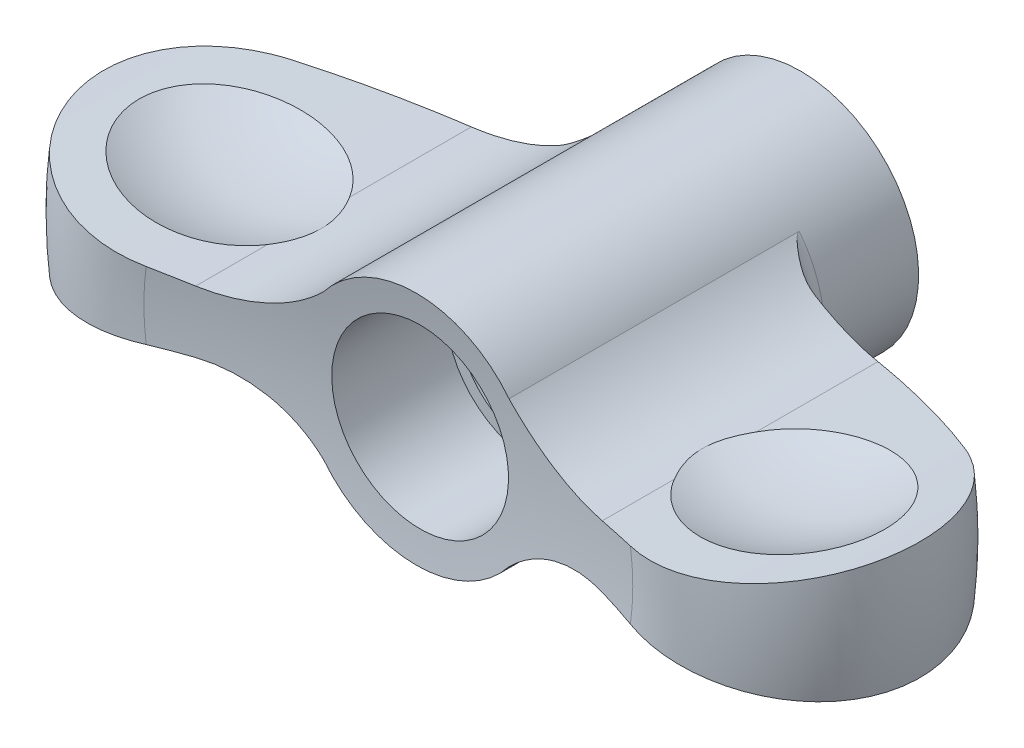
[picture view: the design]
ISO-10303-21;
HEADER;
FILE_DESCRIPTION(('STEP AP214'),'2;1');
FILE_NAME('part.step','',(''),(''),'','','');
FILE_SCHEMA(('AUTOMOTIVE_DESIGN { 1 0 10303 214 1 1 1 1 }'));
ENDSEC;
DATA;
#1=APPLICATION_CONTEXT('core data for automotive mechanical design processes');
#2=APPLICATION_PROTOCOL_DEFINITION('international standard','automotive_design',2000,#1);
#3=PRODUCT_CONTEXT('',#1,'mechanical');
#4=PRODUCT('Part','Part','',(#3));
#5=PRODUCT_RELATED_PRODUCT_CATEGORY('part','',(#4));
#6=PRODUCT_DEFINITION_FORMATION('','',#4);
#7=PRODUCT_DEFINITION_CONTEXT('part definition',#1,'design');
#8=PRODUCT_DEFINITION('design','',#6,#7);
#9=PRODUCT_DEFINITION_SHAPE('','',#8);
#10=(LENGTH_UNIT() NAMED_UNIT(*) SI_UNIT(.MILLI.,.METRE.));
#11=(NAMED_UNIT(*) PLANE_ANGLE_UNIT() SI_UNIT($,.RADIAN.));
#12=(NAMED_UNIT(*) SI_UNIT($,.STERADIAN.) SOLID_ANGLE_UNIT());
#13=UNCERTAINTY_MEASURE_WITH_UNIT(LENGTH_MEASURE(1.E-05),#10,'distance_accuracy_value','');
#14=(GEOMETRIC_REPRESENTATION_CONTEXT(3) GLOBAL_UNCERTAINTY_ASSIGNED_CONTEXT((#13)) GLOBAL_UNIT_ASSIGNED_CONTEXT((#10,
#11,#12)) REPRESENTATION_CONTEXT('',''));
#15=CARTESIAN_POINT('',(0.,0.,0.));
#16=DIRECTION('',(0.,0.,1.));
#17=DIRECTION('',(1.,0.,0.));
#18=AXIS2_PLACEMENT_3D('',#15,#16,#17);
#19=CARTESIAN_POINT('',(0.,0.,8.));
#20=DIRECTION('',(0.,0.,-1.));
#21=DIRECTION('',(0.,1.,0.));
#22=AXIS2_PLACEMENT_3D('',#19,#20,#21);
#23=TOROIDAL_SURFACE('',#22,11.8,1.80000000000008);
#24=CARTESIAN_POINT('',(-10.9364004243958,-3.94636818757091,9.7916319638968));
#25=CARTESIAN_POINT('',(-10.8241185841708,-4.00370429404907,9.78325234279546));
#26=CARTESIAN_POINT('',(-10.7132133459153,-4.06254400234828,9.76897182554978));
#27=CARTESIAN_POINT('',(-10.4947965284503,-4.18269546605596,9.73031315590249));
#28=CARTESIAN_POINT('',(-10.3872790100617,-4.2440024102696,9.70595387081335));
#29=CARTESIAN_POINT('',(-10.1765147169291,-4.368381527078,9.64897611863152));
#30=CARTESIAN_POINT('',(-10.0732455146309,-4.43144032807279,9.61641003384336));
#31=CARTESIAN_POINT('',(-9.87034998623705,-4.55941800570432,9.54423053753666));
#32=CARTESIAN_POINT('',(-9.7707251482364,-4.62433762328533,9.50461428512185));
#33=CARTESIAN_POINT('',(-9.55076497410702,-4.77218804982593,9.4087986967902));
#34=CARTESIAN_POINT('',(-9.43146470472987,-4.8555710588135,9.35092807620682));
#35=CARTESIAN_POINT('',(-9.19845422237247,-5.02453572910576,9.22749490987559));
#36=CARTESIAN_POINT('',(-9.08474708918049,-5.11011856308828,9.16192819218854));
#37=CARTESIAN_POINT('',(-8.8958350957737,-5.25740071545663,9.04459290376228));
#38=CARTESIAN_POINT('',(-8.81922141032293,-5.31864764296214,8.99450670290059));
#39=CARTESIAN_POINT('',(-8.66877804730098,-5.44185241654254,8.89113944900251));
#40=CARTESIAN_POINT('',(-8.5949480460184,-5.50381017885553,8.83785876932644));
#41=CARTESIAN_POINT('',(-8.47417990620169,-5.60755853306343,8.74594898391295));
#42=CARTESIAN_POINT('',(-8.42641392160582,-5.64925103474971,8.7082931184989));
#43=CARTESIAN_POINT('',(-8.33242521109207,-5.73256077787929,8.63109723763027));
#44=CARTESIAN_POINT('',(-8.28620142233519,-5.77417805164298,8.59155856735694));
#45=CARTESIAN_POINT('',(-8.21125367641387,-5.8426693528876,8.52388347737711));
#46=CARTESIAN_POINT('',(-8.18198002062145,-5.86968993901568,8.49650386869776));
#47=CARTESIAN_POINT('',(-8.12444979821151,-5.92330159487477,8.44010631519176));
#48=CARTESIAN_POINT('',(-8.09619524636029,-5.94989176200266,8.41108538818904));
#49=CARTESIAN_POINT('',(-8.04234032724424,-6.00103726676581,8.35179046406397));
#50=CARTESIAN_POINT('',(-8.01668026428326,-6.02563150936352,8.32160361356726));
#51=CARTESIAN_POINT('',(-7.96790958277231,-6.0727602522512,8.2576023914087));
#52=CARTESIAN_POINT('',(-7.94479257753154,-6.0952998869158,8.22379754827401));
#53=CARTESIAN_POINT('',(-7.91701322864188,-6.12255630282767,8.17250880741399));
#54=CARTESIAN_POINT('',(-7.90975258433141,-6.12970126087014,8.15779331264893));
#55=CARTESIAN_POINT('',(-7.89665438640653,-6.14261741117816,8.12727584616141));
#56=CARTESIAN_POINT('',(-7.89080740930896,-6.14839769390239,8.11148202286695));
#57=CARTESIAN_POINT('',(-7.88158226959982,-6.15753000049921,8.08013275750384));
#58=CARTESIAN_POINT('',(-7.87802903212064,-6.16105398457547,8.06468423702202));
#59=CARTESIAN_POINT('',(-7.87307566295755,-6.16597001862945,8.03281428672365));
#60=CARTESIAN_POINT('',(-7.87172008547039,-6.16731795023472,8.01637956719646));
#61=CARTESIAN_POINT('',(-7.8717856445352,-6.16725149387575,7.9998));
#62=B_SPLINE_CURVE_WITH_KNOTS('',3,(#24,#25,#26,#27,#28,#29,#30,#31,#32,#33,#34,#35,#36,#37,#38,
#39,#40,#41,#42,#43,#44,#45,#46,#47,#48,#49,#50,#51,#52,#53,#54,#55,#56,#57,#58,#59,#60,#61),
.UNSPECIFIED.,.F.,.F.,(4,2,2,2,2,2,2,2,2,2,2,2,2,2,2,2,2,2,4),(0.,0.378686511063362,
0.756667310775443,1.13229407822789,1.50807255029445,1.97761636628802,2.44741590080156,
2.77774393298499,3.10803343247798,3.3292309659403,3.55027276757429,3.6952714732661,
3.84054267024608,3.980393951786,4.11988557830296,4.17347981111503,4.2267062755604,
4.27513325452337,4.3245302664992),.UNSPECIFIED.);
#63=CARTESIAN_POINT('',(-10.9337221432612,-3.94773654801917,9.7914319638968));
#64=VERTEX_POINT('',#63);
#65=CARTESIAN_POINT('',(-7.8717855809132,-6.16725155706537,8.));
#66=VERTEX_POINT('',#65);
#67=EDGE_CURVE('E491',#64,#66,#62,.T.);
#68=ORIENTED_EDGE('',*,*,#67,.F.);
#69=CARTESIAN_POINT('',(0.,0.,9.7914319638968));
#70=DIRECTION('',(0.,0.,-1.));
#71=DIRECTION('',(0.,1.,0.));
#72=AXIS2_PLACEMENT_3D('',#69,#70,#71);
#73=CIRCLE('',#72,11.6245818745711);
#74=CARTESIAN_POINT('',(-10.9337221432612,3.94773654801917,9.7914319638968));
#75=VERTEX_POINT('',#74);
#76=EDGE_CURVE('E513',#64,#75,#73,.T.);
#77=ORIENTED_EDGE('',*,*,#76,.T.);
#78=CARTESIAN_POINT('',(-10.9364004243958,3.94636818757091,9.7916319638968));
#79=CARTESIAN_POINT('',(-10.8241185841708,4.00370429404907,9.78325234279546));
#80=CARTESIAN_POINT('',(-10.7132133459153,4.06254400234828,9.76897182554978));
#81=CARTESIAN_POINT('',(-10.4947965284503,4.18269546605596,9.73031315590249));
#82=CARTESIAN_POINT('',(-10.3872790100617,4.24400241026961,9.70595387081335));
#83=CARTESIAN_POINT('',(-10.1765147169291,4.368381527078,9.64897611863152));
#84=CARTESIAN_POINT('',(-10.0732455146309,4.4314403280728,9.61641003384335));
#85=CARTESIAN_POINT('',(-9.87034998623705,4.55941800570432,9.54423053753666));
#86=CARTESIAN_POINT('',(-9.7707251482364,4.62433762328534,9.50461428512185));
#87=CARTESIAN_POINT('',(-9.55076497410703,4.77218804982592,9.4087986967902));
#88=CARTESIAN_POINT('',(-9.4314647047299,4.85557105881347,9.35092807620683));
#89=CARTESIAN_POINT('',(-9.19845422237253,5.02453572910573,9.22749490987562));
#90=CARTESIAN_POINT('',(-9.08474708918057,5.11011856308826,9.16192819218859));
#91=CARTESIAN_POINT('',(-8.89583509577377,5.25740071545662,9.04459290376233));
#92=CARTESIAN_POINT('',(-8.81922141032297,5.31864764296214,8.99450670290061));
#93=CARTESIAN_POINT('',(-8.66877804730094,5.44185241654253,8.89113944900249));
#94=CARTESIAN_POINT('',(-8.59494804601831,5.50381017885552,8.83785876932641));
#95=CARTESIAN_POINT('',(-8.47417990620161,5.60755853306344,8.74594898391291));
#96=CARTESIAN_POINT('',(-8.42641392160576,5.64925103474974,8.70829311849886));
#97=CARTESIAN_POINT('',(-8.33242521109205,5.73256077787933,8.63109723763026));
#98=CARTESIAN_POINT('',(-8.28620142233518,5.774178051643,8.59155856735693));
#99=CARTESIAN_POINT('',(-8.21125367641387,5.8426693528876,8.52388347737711));
#100=CARTESIAN_POINT('',(-8.18198002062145,5.86968993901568,8.49650386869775));
#101=CARTESIAN_POINT('',(-8.1244497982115,5.92330159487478,8.44010631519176));
#102=CARTESIAN_POINT('',(-8.09619524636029,5.94989176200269,8.41108538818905));
#103=CARTESIAN_POINT('',(-8.04234032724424,6.00103726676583,8.35179046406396));
#104=CARTESIAN_POINT('',(-8.01668026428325,6.02563150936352,8.32160361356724));
#105=CARTESIAN_POINT('',(-7.9679095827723,6.07276025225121,8.25760239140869));
#106=CARTESIAN_POINT('',(-7.94479257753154,6.09529988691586,8.22379754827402));
#107=CARTESIAN_POINT('',(-7.91701322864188,6.12255630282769,8.17250880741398));
#108=CARTESIAN_POINT('',(-7.90975258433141,6.12970126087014,8.15779331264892));
#109=CARTESIAN_POINT('',(-7.89665438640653,6.14261741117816,8.1272758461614));
#110=CARTESIAN_POINT('',(-7.89080740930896,6.14839769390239,8.11148202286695));
#111=CARTESIAN_POINT('',(-7.88158226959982,6.15753000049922,8.08013275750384));
#112=CARTESIAN_POINT('',(-7.87802903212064,6.16105398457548,8.06468423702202));
#113=CARTESIAN_POINT('',(-7.87307566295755,6.16597001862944,8.03281428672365));
#114=CARTESIAN_POINT('',(-7.8717200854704,6.16731795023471,8.01637956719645));
#115=CARTESIAN_POINT('',(-7.8717856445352,6.16725149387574,7.9998));
#116=B_SPLINE_CURVE_WITH_KNOTS('',3,(#78,#79,#80,#81,#82,#83,#84,#85,#86,#87,#88,#89,#90,#91,
#92,#93,#94,#95,#96,#97,#98,#99,#100,#101,#102,#103,#104,#105,#106,#107,#108,#109,#110,#111,
#112,#113,#114,#115),.UNSPECIFIED.,.F.,.F.,(4,2,2,2,2,2,2,2,2,2,2,2,2,2,2,2,2,2,4),(0.,
0.378686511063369,0.756667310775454,1.1322940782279,1.50807255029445,1.97761636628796,
2.44741590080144,2.77774393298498,3.10803343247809,3.32923096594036,3.55027276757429,
3.6952714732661,3.84054267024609,3.98039395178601,4.11988557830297,4.17347981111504,
4.22670627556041,4.27513325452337,4.3245302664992),.UNSPECIFIED.);
#117=CARTESIAN_POINT('',(-7.8717855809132,6.16725155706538,8.));
#118=VERTEX_POINT('',#117);
#119=EDGE_CURVE('E318',#75,#118,#116,.T.);
#120=ORIENTED_EDGE('',*,*,#119,.T.);
#121=CARTESIAN_POINT('',(0.,0.,8.));
#122=DIRECTION('',(0.,0.,-1.));
#123=DIRECTION('',(0.,1.,0.));
#124=AXIS2_PLACEMENT_3D('',#121,#122,#123);
#125=CIRCLE('',#124,10.);
#126=EDGE_CURVE('E438',#66,#118,#125,.T.);
#127=ORIENTED_EDGE('',*,*,#126,.F.);
#128=EDGE_LOOP('',(#68,#77,#120,#127));
#129=FACE_BOUND('',#128,.T.);
#130=ADVANCED_FACE('F14',(#129),#23,.F.);
#131=CARTESIAN_POINT('',(0.,0.,60.3122983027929));
#132=DIRECTION('',(0.,0.,-1.));
#133=DIRECTION('',(0.,1.,0.));
#134=AXIS2_PLACEMENT_3D('',#131,#132,#133);
#135=DEGENERATE_TOROIDAL_SURFACE('',#134,6.6775474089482,50.7624968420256,.T.);
#136=ORIENTED_EDGE('',*,*,#76,.F.);
#137=CARTESIAN_POINT('',(-6.5467060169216,-7.72330133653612,9.66697769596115));
#138=CARTESIAN_POINT('',(-6.64591288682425,-7.58492422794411,9.66416255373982));
#139=CARTESIAN_POINT('',(-6.74799440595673,-7.44862247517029,9.661900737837));
#140=CARTESIAN_POINT('',(-6.95774811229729,-7.18037757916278,9.65844214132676));
#141=CARTESIAN_POINT('',(-7.06542027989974,-7.04843442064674,9.6572453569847));
#142=CARTESIAN_POINT('',(-7.39653737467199,-6.6595102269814,9.65519040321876));
#143=CARTESIAN_POINT('',(-7.62812663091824,-6.40937348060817,9.65586643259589));
#144=CARTESIAN_POINT('',(-8.11129299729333,-5.92925394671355,9.66138002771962));
#145=CARTESIAN_POINT('',(-8.36287299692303,-5.69927408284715,9.66621819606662));
#146=CARTESIAN_POINT('',(-8.88421895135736,-5.26109545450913,9.68055080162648));
#147=CARTESIAN_POINT('',(-9.15398440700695,-5.05289609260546,9.69004511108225));
#148=CARTESIAN_POINT('',(-9.70731186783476,-4.66146851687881,9.71434109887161));
#149=CARTESIAN_POINT('',(-9.99073342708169,-4.47803881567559,9.72909588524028));
#150=CARTESIAN_POINT('',(-10.5714417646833,-4.13530031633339,9.76473262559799));
#151=CARTESIAN_POINT('',(-10.8687285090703,-3.97599145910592,9.78561456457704));
#152=CARTESIAN_POINT('',(-11.4746831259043,-3.68269992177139,9.83420440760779));
#153=CARTESIAN_POINT('',(-11.7833407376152,-3.54869504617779,9.86190627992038));
#154=CARTESIAN_POINT('',(-12.4099583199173,-3.30668939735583,9.92468529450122));
#155=CARTESIAN_POINT('',(-12.72791823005,-3.19868845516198,9.95976238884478));
#156=CARTESIAN_POINT('',(-13.3702784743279,-3.00943594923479,10.0375625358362));
#157=CARTESIAN_POINT('',(-13.694668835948,-2.92814595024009,10.080274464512));
#158=CARTESIAN_POINT('',(-14.3479208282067,-2.7924555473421,10.173495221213));
#159=CARTESIAN_POINT('',(-14.6767824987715,-2.73805538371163,10.2240041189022));
#160=CARTESIAN_POINT('',(-15.3369192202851,-2.65620760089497,10.3328061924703));
#161=CARTESIAN_POINT('',(-15.6681964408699,-2.62878831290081,10.3911074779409));
#162=CARTESIAN_POINT('',(-16.3304789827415,-2.60086726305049,10.5152293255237));
#163=CARTESIAN_POINT('',(-16.6614842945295,-2.60036640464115,10.5810501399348));
#164=CARTESIAN_POINT('',(-17.3240428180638,-2.62605289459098,10.7205107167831));
#165=CARTESIAN_POINT('',(-17.6555720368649,-2.65249066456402,10.7942180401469));
#166=CARTESIAN_POINT('',(-18.3138495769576,-2.73187573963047,10.9484805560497));
#167=CARTESIAN_POINT('',(-18.6405974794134,-2.78482535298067,11.0290363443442));
#168=CARTESIAN_POINT('',(-19.2867879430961,-2.91642655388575,11.1963521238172));
#169=CARTESIAN_POINT('',(-19.6062391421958,-2.99504586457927,11.2831042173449));
#170=CARTESIAN_POINT('',(-20.2362844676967,-3.17708996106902,11.4622866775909));
#171=CARTESIAN_POINT('',(-20.5468805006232,-3.28050936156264,11.5547158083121));
#172=CARTESIAN_POINT('',(-20.8521318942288,-3.39588894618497,11.6496949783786));
#173=B_SPLINE_CURVE_WITH_KNOTS('',3,(#137,#138,#139,#140,#141,#142,#143,#144,#145,#146,#147,
#148,#149,#150,#151,#152,#153,#154,#155,#156,#157,#158,#159,#160,#161,#162,#163,#164,#165,#166,
#167,#168,#169,#170,#171,#172),.UNSPECIFIED.,.F.,.F.,(4,2,2,2,2,2,2,2,2,2,2,2,2,2,2,2,2,4),(0.,
0.510785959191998,1.02157012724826,2.04291399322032,3.06440575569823,4.08586949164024,
5.09844663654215,6.11102130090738,7.12270361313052,8.13437935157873,9.14459291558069,
10.1548155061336,11.1660977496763,12.1774139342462,13.1982178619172,14.2191106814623,
15.2387247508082,16.2581176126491),.UNSPECIFIED.);
#174=CARTESIAN_POINT('',(-17.2513916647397,-2.62600423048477,10.7060191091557));
#175=VERTEX_POINT('',#174);
#176=EDGE_CURVE('E485',#64,#175,#173,.T.);
#177=ORIENTED_EDGE('',*,*,#176,.T.);
#178=CARTESIAN_POINT('',(-28.5420587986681,-3.86093353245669,14.6248916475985));
#179=CARTESIAN_POINT('',(-28.0949251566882,-3.78973654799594,14.4056959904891));
#180=CARTESIAN_POINT('',(-27.6441940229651,-3.72065339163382,14.1932196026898));
#181=CARTESIAN_POINT('',(-26.7359054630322,-3.58698745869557,13.7818878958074));
#182=CARTESIAN_POINT('',(-26.2783480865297,-3.52240464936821,13.583032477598));
#183=CARTESIAN_POINT('',(-24.8998297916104,-3.33633398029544,13.0087706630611));
#184=CARTESIAN_POINT('',(-23.9692804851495,-3.22192463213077,12.6538347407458));
#185=CARTESIAN_POINT('',(-22.0863023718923,-3.01405683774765,12.0002442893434));
#186=CARTESIAN_POINT('',(-21.133873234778,-2.92059870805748,11.701590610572));
#187=CARTESIAN_POINT('',(-19.6898454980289,-2.79722984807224,11.296179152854));
#188=CARTESIAN_POINT('',(-19.2049108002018,-2.75884755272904,11.1679139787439));
#189=CARTESIAN_POINT('',(-18.2309836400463,-2.68796520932,10.9259763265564));
#190=CARTESIAN_POINT('',(-17.7419911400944,-2.65546521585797,10.8123039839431));
#191=CARTESIAN_POINT('',(-17.2511916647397,-2.6259922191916,10.7059757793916));
#192=B_SPLINE_CURVE_WITH_KNOTS('',3,(#178,#179,#180,#181,#182,#183,#184,#185,#186,#187,#188,
#189,#190,#191),.UNSPECIFIED.,.F.,.F.,(4,2,2,2,2,2,4),(0.,1.50898291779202,3.01795485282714,
6.0232908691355,9.02867228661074,10.5376740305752,12.0466897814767),.UNSPECIFIED.);
#193=CARTESIAN_POINT('',(-28.5416508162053,-3.86086857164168,14.6246916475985));
#194=VERTEX_POINT('',#193);
#195=EDGE_CURVE('E524',#194,#175,#192,.T.);
#196=ORIENTED_EDGE('',*,*,#195,.F.);
#197=CARTESIAN_POINT('',(0.,0.,14.6246916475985));
#198=DIRECTION('',(0.,0.,-1.));
#199=DIRECTION('',(0.,1.,0.));
#200=AXIS2_PLACEMENT_3D('',#197,#198,#199);
#201=CIRCLE('',#200,28.8015995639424);
#202=CARTESIAN_POINT('',(-28.5416508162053,3.86086857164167,14.6246916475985));
#203=VERTEX_POINT('',#202);
#204=EDGE_CURVE('E511',#194,#203,#201,.T.);
#205=ORIENTED_EDGE('',*,*,#204,.T.);
#206=CARTESIAN_POINT('',(-28.5420587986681,3.86093353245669,14.6248916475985));
#207=CARTESIAN_POINT('',(-28.0949251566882,3.78973654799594,14.4056959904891));
#208=CARTESIAN_POINT('',(-27.6441940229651,3.72065339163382,14.1932196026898));
#209=CARTESIAN_POINT('',(-26.7359054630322,3.58698745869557,13.7818878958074));
#210=CARTESIAN_POINT('',(-26.2783480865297,3.5224046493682,13.583032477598));
#211=CARTESIAN_POINT('',(-24.8998297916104,3.33633398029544,13.0087706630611));
#212=CARTESIAN_POINT('',(-23.9692804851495,3.22192463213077,12.6538347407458));
#213=CARTESIAN_POINT('',(-22.0863023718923,3.01405683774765,12.0002442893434));
#214=CARTESIAN_POINT('',(-21.133873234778,2.92059870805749,11.701590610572));
#215=CARTESIAN_POINT('',(-19.6898454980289,2.79722984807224,11.296179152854));
#216=CARTESIAN_POINT('',(-19.2049108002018,2.75884755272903,11.1679139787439));
#217=CARTESIAN_POINT('',(-18.2309836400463,2.68796520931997,10.9259763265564));
#218=CARTESIAN_POINT('',(-17.7419911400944,2.65546521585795,10.8123039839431));
#219=CARTESIAN_POINT('',(-17.2511916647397,2.62599221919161,10.7059757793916));
#220=B_SPLINE_CURVE_WITH_KNOTS('',3,(#206,#207,#208,#209,#210,#211,#212,#213,#214,#215,#216,
#217,#218,#219),.UNSPECIFIED.,.F.,.F.,(4,2,2,2,2,2,4),(0.,1.50898291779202,3.01795485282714,
6.0232908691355,9.02867228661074,10.5376740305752,12.0466897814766),.UNSPECIFIED.);
#221=CARTESIAN_POINT('',(-17.2513916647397,2.62600423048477,10.7060191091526));
#222=VERTEX_POINT('',#221);
#223=EDGE_CURVE('E332',#203,#222,#220,.T.);
#224=ORIENTED_EDGE('',*,*,#223,.T.);
#225=CARTESIAN_POINT('',(-6.5467060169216,7.72330133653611,9.66697769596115));
#226=CARTESIAN_POINT('',(-6.64591288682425,7.5849242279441,9.66416255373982));
#227=CARTESIAN_POINT('',(-6.74799440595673,7.44862247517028,9.661900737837));
#228=CARTESIAN_POINT('',(-6.9577481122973,7.18037757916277,9.65844214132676));
#229=CARTESIAN_POINT('',(-7.06542027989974,7.04843442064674,9.6572453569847));
#230=CARTESIAN_POINT('',(-7.39653737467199,6.65951022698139,9.65519040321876));
#231=CARTESIAN_POINT('',(-7.62812663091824,6.40937348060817,9.65586643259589));
#232=CARTESIAN_POINT('',(-8.11129299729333,5.92925394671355,9.66138002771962));
#233=CARTESIAN_POINT('',(-8.36287299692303,5.69927408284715,9.66621819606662));
#234=CARTESIAN_POINT('',(-8.88421895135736,5.26109545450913,9.68055080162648));
#235=CARTESIAN_POINT('',(-9.15398440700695,5.05289609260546,9.69004511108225));
#236=CARTESIAN_POINT('',(-9.70731186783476,4.66146851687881,9.71434109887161));
#237=CARTESIAN_POINT('',(-9.99073342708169,4.47803881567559,9.72909588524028));
#238=CARTESIAN_POINT('',(-10.5714417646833,4.13530031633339,9.76473262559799));
#239=CARTESIAN_POINT('',(-10.8687285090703,3.97599145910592,9.78561456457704));
#240=CARTESIAN_POINT('',(-11.4746831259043,3.68269992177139,9.83420440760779));
#241=CARTESIAN_POINT('',(-11.7833407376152,3.54869504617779,9.86190627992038));
#242=CARTESIAN_POINT('',(-12.4099583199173,3.30668939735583,9.92468529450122));
#243=CARTESIAN_POINT('',(-12.72791823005,3.19868845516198,9.95976238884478));
#244=CARTESIAN_POINT('',(-13.3702784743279,3.00943594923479,10.0375625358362));
#245=CARTESIAN_POINT('',(-13.694668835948,2.92814595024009,10.080274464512));
#246=CARTESIAN_POINT('',(-14.3479208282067,2.7924555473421,10.173495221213));
#247=CARTESIAN_POINT('',(-14.6767824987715,2.73805538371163,10.2240041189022));
#248=CARTESIAN_POINT('',(-15.3369192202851,2.65620760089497,10.3328061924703));
#249=CARTESIAN_POINT('',(-15.6681964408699,2.62878831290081,10.3911074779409));
#250=CARTESIAN_POINT('',(-16.3304789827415,2.60086726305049,10.5152293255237));
#251=CARTESIAN_POINT('',(-16.6614842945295,2.60036640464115,10.5810501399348));
#252=CARTESIAN_POINT('',(-17.3240428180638,2.62605289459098,10.7205107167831));
#253=CARTESIAN_POINT('',(-17.6555720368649,2.65249066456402,10.7942180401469));
#254=CARTESIAN_POINT('',(-18.3138495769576,2.73187573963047,10.9484805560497));
#255=CARTESIAN_POINT('',(-18.6405974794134,2.78482535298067,11.0290363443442));
#256=CARTESIAN_POINT('',(-19.2867879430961,2.91642655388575,11.1963521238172));
#257=CARTESIAN_POINT('',(-19.6062391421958,2.99504586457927,11.2831042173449));
#258=CARTESIAN_POINT('',(-20.2362844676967,3.17708996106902,11.4622866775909));
#259=CARTESIAN_POINT('',(-20.5468805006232,3.28050936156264,11.5547158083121));
#260=CARTESIAN_POINT('',(-20.8521318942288,3.39588894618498,11.6496949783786));
#261=B_SPLINE_CURVE_WITH_KNOTS('',3,(#225,#226,#227,#228,#229,#230,#231,#232,#233,#234,#235,
#236,#237,#238,#239,#240,#241,#242,#243,#244,#245,#246,#247,#248,#249,#250,#251,#252,#253,#254,
#255,#256,#257,#258,#259,#260),.UNSPECIFIED.,.F.,.F.,(4,2,2,2,2,2,2,2,2,2,2,2,2,2,2,2,2,4),(0.,
0.510785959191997,1.02157012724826,2.04291399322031,3.06440575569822,4.08586949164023,
5.09844663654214,6.11102130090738,7.12270361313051,8.13437935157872,9.14459291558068,
10.1548155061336,11.1660977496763,12.1774139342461,13.1982178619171,14.2191106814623,
15.2387247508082,16.2581176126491),.UNSPECIFIED.);
#262=EDGE_CURVE('E301',#75,#222,#261,.T.);
#263=ORIENTED_EDGE('',*,*,#262,.F.);
#264=EDGE_LOOP('',(#136,#177,#196,#205,#224,#263));
#265=FACE_BOUND('',#264,.T.);
#266=ADVANCED_FACE('F521',(#265),#135,.T.);
#267=CARTESIAN_POINT('',(0.,0.,24.5131504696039));
#268=DIRECTION('',(0.,0.,-1.));
#269=DIRECTION('',(0.,1.,0.));
#270=AXIS2_PLACEMENT_3D('',#267,#268,#269);
#271=TOROIDAL_SURFACE('',#270,24.0131504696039,10.9868495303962);
#272=CARTESIAN_POINT('',(-17.2511916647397,-2.62599221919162,33.3242100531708));
#273=CARTESIAN_POINT('',(-17.4993781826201,-2.64089075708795,33.5086851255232));
#274=CARTESIAN_POINT('',(-17.7552628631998,-2.65706460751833,33.6826969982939));
#275=CARTESIAN_POINT('',(-18.28053769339,-2.69210530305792,34.0086627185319));
#276=CARTESIAN_POINT('',(-18.5499277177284,-2.71097212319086,34.1606167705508));
#277=CARTESIAN_POINT('',(-19.1002002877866,-2.75153205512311,34.4412740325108));
#278=CARTESIAN_POINT('',(-19.381077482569,-2.77322386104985,34.5699879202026));
#279=CARTESIAN_POINT('',(-19.952432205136,-2.81952002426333,34.8033129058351));
#280=CARTESIAN_POINT('',(-20.2429095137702,-2.84412431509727,34.9079245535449));
#281=CARTESIAN_POINT('',(-20.8315983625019,-2.89628797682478,35.0923323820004));
#282=CARTESIAN_POINT('',(-21.1298150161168,-2.92384934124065,35.1721116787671));
#283=CARTESIAN_POINT('',(-21.7316508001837,-2.98187199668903,35.3061577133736));
#284=CARTESIAN_POINT('',(-22.035269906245,-3.01233327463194,35.3604245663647));
#285=CARTESIAN_POINT('',(-22.6456357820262,-3.0760359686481,35.4430189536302));
#286=CARTESIAN_POINT('',(-22.9523815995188,-3.10927655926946,35.4713541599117));
#287=CARTESIAN_POINT('',(-23.566877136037,-3.17836345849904,35.501889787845));
#288=CARTESIAN_POINT('',(-23.874626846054,-3.21420974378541,35.504090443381));
#289=CARTESIAN_POINT('',(-24.4874432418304,-3.28807700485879,35.4823817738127));
#290=CARTESIAN_POINT('',(-24.7925157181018,-3.32608674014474,35.4585974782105));
#291=CARTESIAN_POINT('',(-25.3992908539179,-3.404117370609,35.3852808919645));
#292=CARTESIAN_POINT('',(-25.7009935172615,-3.44413826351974,35.3357486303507));
#293=CARTESIAN_POINT('',(-26.2989412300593,-3.52581537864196,35.211278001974));
#294=CARTESIAN_POINT('',(-26.595185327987,-3.56747188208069,35.1363352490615));
#295=CARTESIAN_POINT('',(-27.1800717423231,-3.65197221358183,34.9615826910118));
#296=CARTESIAN_POINT('',(-27.4687140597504,-3.69481604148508,34.8617728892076));
#297=CARTESIAN_POINT('',(-28.035952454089,-3.78113479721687,34.6381665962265));
#298=CARTESIAN_POINT('',(-28.3145627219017,-3.82460870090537,34.514405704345));
#299=CARTESIAN_POINT('',(-28.8602471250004,-3.9117173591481,34.2436848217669));
#300=CARTESIAN_POINT('',(-29.1273212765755,-3.9553521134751,34.0967248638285));
#301=CARTESIAN_POINT('',(-29.6480727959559,-4.04221651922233,33.7806574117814));
#302=CARTESIAN_POINT('',(-29.9017509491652,-4.08544619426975,33.6115512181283));
#303=CARTESIAN_POINT('',(-30.3939845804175,-4.17091924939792,33.2523788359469));
#304=CARTESIAN_POINT('',(-30.6325400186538,-4.21316262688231,33.0623125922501));
#305=CARTESIAN_POINT('',(-31.0935716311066,-4.29619199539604,32.6619711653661));
#306=CARTESIAN_POINT('',(-31.3159985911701,-4.33697334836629,32.4516383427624));
#307=CARTESIAN_POINT('',(-31.7424740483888,-4.41635307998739,32.0127202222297));
#308=CARTESIAN_POINT('',(-31.9465225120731,-4.45495145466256,31.7841348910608));
#309=CARTESIAN_POINT('',(-32.3348520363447,-4.52938773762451,31.3103146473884));
#310=CARTESIAN_POINT('',(-32.5191323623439,-4.56522554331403,31.0650791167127));
#311=CARTESIAN_POINT('',(-32.8666572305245,-4.63358841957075,30.5596945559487));
#312=CARTESIAN_POINT('',(-33.0299017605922,-4.66611348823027,30.2995455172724));
#313=CARTESIAN_POINT('',(-33.3345075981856,-4.72739462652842,29.7656976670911));
#314=CARTESIAN_POINT('',(-33.4758297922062,-4.75614394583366,29.4919757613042));
#315=CARTESIAN_POINT('',(-33.7352733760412,-4.80934524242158,28.9333467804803));
#316=CARTESIAN_POINT('',(-33.8533947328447,-4.83379721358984,28.6484396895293));
#317=CARTESIAN_POINT('',(-34.0656204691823,-4.87800530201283,28.0694731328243));
#318=CARTESIAN_POINT('',(-34.1597255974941,-4.89776156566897,27.7754139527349));
#319=CARTESIAN_POINT('',(-34.3232748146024,-4.93225390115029,27.180228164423));
#320=CARTESIAN_POINT('',(-34.3927189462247,-4.94698998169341,26.8791015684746));
#321=CARTESIAN_POINT('',(-34.5063857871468,-4.97117989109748,26.2723608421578));
#322=CARTESIAN_POINT('',(-34.5506442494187,-4.98064120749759,25.96675370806));
#323=CARTESIAN_POINT('',(-34.6137870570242,-4.99415603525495,25.3528106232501));
#324=CARTESIAN_POINT('',(-34.6326714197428,-4.99820955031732,25.0444746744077));
#325=CARTESIAN_POINT('',(-34.644935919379,-5.00084099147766,24.4272603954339));
#326=CARTESIAN_POINT('',(-34.6383150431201,-4.99941870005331,24.1183820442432));
#327=CARTESIAN_POINT('',(-34.5996125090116,-4.9911218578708,23.5022985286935));
#328=CARTESIAN_POINT('',(-34.5675308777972,-4.98424731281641,23.1950933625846));
#329=CARTESIAN_POINT('',(-34.4781950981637,-4.96517513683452,22.5850017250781));
#330=CARTESIAN_POINT('',(-34.4209785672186,-4.95298546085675,22.2821094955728));
#331=CARTESIAN_POINT('',(-34.2817747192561,-4.92348679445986,21.6823260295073));
#332=CARTESIAN_POINT('',(-34.1997873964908,-4.90617780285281,21.3854347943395));
#333=CARTESIAN_POINT('',(-34.0116119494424,-4.86672680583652,20.799780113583));
#334=CARTESIAN_POINT('',(-33.9054257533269,-4.84458518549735,20.5110160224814));
#335=CARTESIAN_POINT('',(-33.6695763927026,-4.79582854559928,19.9436331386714));
#336=CARTESIAN_POINT('',(-33.5399133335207,-4.76921354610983,19.665014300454));
#337=CARTESIAN_POINT('',(-33.2578321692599,-4.71190410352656,19.1195687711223));
#338=CARTESIAN_POINT('',(-33.1053878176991,-4.68120495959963,18.8527561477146));
#339=CARTESIAN_POINT('',(-32.7788934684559,-4.61623623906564,18.3331441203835));
#340=CARTESIAN_POINT('',(-32.6048429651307,-4.58196657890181,18.0803450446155));
#341=CARTESIAN_POINT('',(-32.2363296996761,-4.5103897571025,17.5905487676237));
#342=CARTESIAN_POINT('',(-32.0418667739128,-4.47308257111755,17.3535516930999));
#343=CARTESIAN_POINT('',(-31.633867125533,-4.39599896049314,16.8970435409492));
#344=CARTESIAN_POINT('',(-31.4203320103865,-4.35622274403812,16.6775309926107));
#345=CARTESIAN_POINT('',(-31.0011481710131,-4.27945832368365,16.2816097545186));
#346=CARTESIAN_POINT('',(-30.797399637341,-4.24267293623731,16.103144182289));
#347=CARTESIAN_POINT('',(-30.377205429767,-4.16804353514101,15.7621159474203));
#348=CARTESIAN_POINT('',(-30.1607608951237,-4.13019961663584,15.5995518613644));
#349=CARTESIAN_POINT('',(-29.7163820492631,-4.05387450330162,15.2912603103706));
#350=CARTESIAN_POINT('',(-29.4884504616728,-4.01539346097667,15.1455288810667));
#351=CARTESIAN_POINT('',(-29.0222683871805,-3.93818298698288,14.871631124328));
#352=CARTESIAN_POINT('',(-28.7840165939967,-3.89945352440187,14.7434670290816));
#353=CARTESIAN_POINT('',(-28.5412428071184,-3.86080360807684,14.6244916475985));
#354=B_SPLINE_CURVE_WITH_KNOTS('',3,(#272,#273,#274,#275,#276,#277,#278,#279,#280,#281,#282,
#283,#284,#285,#286,#287,#288,#289,#290,#291,#292,#293,#294,#295,#296,#297,#298,#299,#300,#301,
#302,#303,#304,#305,#306,#307,#308,#309,#310,#311,#312,#313,#314,#315,#316,#317,#318,#319,#320,
#321,#322,#323,#324,#325,#326,#327,#328,#329,#330,#331,#332,#333,#334,#335,#336,#337,#338,#339,
#340,#341,#342,#343,#344,#345,#346,#347,#348,#349,#350,#351,#352,#353),.UNSPECIFIED.,.F.,.F.,(4,
2,2,2,2,2,2,2,2,2,2,2,2,2,2,2,2,2,2,2,2,2,2,2,2,2,2,2,2,2,2,2,2,2,2,2,2,2,2,2,4),(0.,
0.928513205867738,1.85701780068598,2.7850947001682,3.7131504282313,4.64183578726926,
5.57051695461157,6.49892327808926,7.42732129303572,8.35127181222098,9.27522128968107,
10.1993303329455,11.1234392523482,12.0461850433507,12.9689295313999,13.8916198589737,
14.8143126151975,15.7397117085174,16.6651124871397,17.5905476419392,18.5159833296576,
19.4430516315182,20.3701212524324,21.2971619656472,22.2242010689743,23.1499208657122,
24.0756400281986,25.0013959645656,25.9271509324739,26.8515250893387,27.7758994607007,
28.7002002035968,29.6244967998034,30.5498666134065,31.4752580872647,32.4006569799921,
33.3259779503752,34.1452666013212,34.9644818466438,35.7835037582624,36.6026296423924),.UNSPECIFIED.);
#355=CARTESIAN_POINT('',(-20.5453214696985,-2.87092129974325,35.0026521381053));
#356=VERTEX_POINT('',#355);
#357=EDGE_CURVE('E527',#356,#194,#354,.T.);
#358=ORIENTED_EDGE('',*,*,#357,.F.);
#359=CARTESIAN_POINT('',(0.,0.,35.0026521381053));
#360=DIRECTION('',(0.,0.,-1.));
#361=DIRECTION('',(0.,1.,0.));
#362=AXIS2_PLACEMENT_3D('',#359,#360,#361);
#363=CIRCLE('',#362,20.7449372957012);
#364=CARTESIAN_POINT('',(-20.5453214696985,2.87092129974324,35.0026521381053));
#365=VERTEX_POINT('',#364);
#366=EDGE_CURVE('E509',#356,#365,#363,.T.);
#367=ORIENTED_EDGE('',*,*,#366,.T.);
#368=CARTESIAN_POINT('',(-17.2511916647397,2.6259922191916,33.3242100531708));
#369=CARTESIAN_POINT('',(-17.4993781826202,2.64089075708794,33.5086851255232));
#370=CARTESIAN_POINT('',(-17.7552628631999,2.65706460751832,33.6826969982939));
#371=CARTESIAN_POINT('',(-18.28053769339,2.69210530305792,34.0086627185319));
#372=CARTESIAN_POINT('',(-18.5499277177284,2.71097212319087,34.1606167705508));
#373=CARTESIAN_POINT('',(-19.1002002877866,2.75153205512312,34.4412740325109));
#374=CARTESIAN_POINT('',(-19.3810774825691,2.77322386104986,34.5699879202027));
#375=CARTESIAN_POINT('',(-19.952432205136,2.81952002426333,34.8033129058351));
#376=CARTESIAN_POINT('',(-20.2429095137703,2.84412431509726,34.9079245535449));
#377=CARTESIAN_POINT('',(-20.831598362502,2.89628797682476,35.0923323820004));
#378=CARTESIAN_POINT('',(-21.1298150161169,2.92384934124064,35.1721116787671));
#379=CARTESIAN_POINT('',(-21.7316508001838,2.98187199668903,35.3061577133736));
#380=CARTESIAN_POINT('',(-22.0352699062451,3.01233327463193,35.3604245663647));
#381=CARTESIAN_POINT('',(-22.6456357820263,3.0760359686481,35.4430189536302));
#382=CARTESIAN_POINT('',(-22.9523815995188,3.10927655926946,35.4713541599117));
#383=CARTESIAN_POINT('',(-23.566877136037,3.17836345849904,35.501889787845));
#384=CARTESIAN_POINT('',(-23.874626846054,3.21420974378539,35.504090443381));
#385=CARTESIAN_POINT('',(-24.4874432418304,3.28807700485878,35.4823817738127));
#386=CARTESIAN_POINT('',(-24.7925157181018,3.32608674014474,35.4585974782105));
#387=CARTESIAN_POINT('',(-25.3992908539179,3.40411737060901,35.3852808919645));
#388=CARTESIAN_POINT('',(-25.7009935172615,3.44413826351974,35.3357486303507));
#389=CARTESIAN_POINT('',(-26.2989412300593,3.52581537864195,35.211278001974));
#390=CARTESIAN_POINT('',(-26.595185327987,3.56747188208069,35.1363352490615));
#391=CARTESIAN_POINT('',(-27.1800717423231,3.65197221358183,34.9615826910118));
#392=CARTESIAN_POINT('',(-27.4687140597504,3.69481604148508,34.8617728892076));
#393=CARTESIAN_POINT('',(-28.035952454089,3.78113479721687,34.6381665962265));
#394=CARTESIAN_POINT('',(-28.3145627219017,3.82460870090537,34.514405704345));
#395=CARTESIAN_POINT('',(-28.8602471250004,3.9117173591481,34.2436848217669));
#396=CARTESIAN_POINT('',(-29.1273212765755,3.9553521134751,34.0967248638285));
#397=CARTESIAN_POINT('',(-29.6480727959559,4.04221651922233,33.7806574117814));
#398=CARTESIAN_POINT('',(-29.9017509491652,4.08544619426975,33.6115512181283));
#399=CARTESIAN_POINT('',(-30.3939845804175,4.17091924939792,33.2523788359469));
#400=CARTESIAN_POINT('',(-30.6325400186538,4.21316262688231,33.0623125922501));
#401=CARTESIAN_POINT('',(-31.0935716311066,4.29619199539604,32.6619711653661));
#402=CARTESIAN_POINT('',(-31.3159985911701,4.33697334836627,32.4516383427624));
#403=CARTESIAN_POINT('',(-31.7424740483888,4.41635307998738,32.0127202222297));
#404=CARTESIAN_POINT('',(-31.9465225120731,4.45495145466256,31.7841348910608));
#405=CARTESIAN_POINT('',(-32.3348520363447,4.52938773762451,31.3103146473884));
#406=CARTESIAN_POINT('',(-32.5191323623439,4.56522554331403,31.0650791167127));
#407=CARTESIAN_POINT('',(-32.8666572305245,4.63358841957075,30.5596945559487));
#408=CARTESIAN_POINT('',(-33.0299017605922,4.66611348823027,30.2995455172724));
#409=CARTESIAN_POINT('',(-33.3345075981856,4.72739462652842,29.7656976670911));
#410=CARTESIAN_POINT('',(-33.4758297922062,4.75614394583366,29.4919757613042));
#411=CARTESIAN_POINT('',(-33.7352733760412,4.80934524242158,28.9333467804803));
#412=CARTESIAN_POINT('',(-33.8533947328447,4.83379721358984,28.6484396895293));
#413=CARTESIAN_POINT('',(-34.0656204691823,4.87800530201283,28.0694731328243));
#414=CARTESIAN_POINT('',(-34.1597255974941,4.89776156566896,27.7754139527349));
#415=CARTESIAN_POINT('',(-34.3232748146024,4.93225390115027,27.180228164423));
#416=CARTESIAN_POINT('',(-34.3927189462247,4.94698998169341,26.8791015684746));
#417=CARTESIAN_POINT('',(-34.5063857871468,4.97117989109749,26.2723608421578));
#418=CARTESIAN_POINT('',(-34.5506442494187,4.98064120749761,25.96675370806));
#419=CARTESIAN_POINT('',(-34.6137870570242,4.99415603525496,25.3528106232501));
#420=CARTESIAN_POINT('',(-34.6326714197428,4.99820955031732,25.0444746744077));
#421=CARTESIAN_POINT('',(-34.644935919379,5.00084099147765,24.4272603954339));
#422=CARTESIAN_POINT('',(-34.6383150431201,4.9994187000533,24.1183820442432));
#423=CARTESIAN_POINT('',(-34.5996125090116,4.99112185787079,23.5022985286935));
#424=CARTESIAN_POINT('',(-34.5675308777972,4.98424731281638,23.1950933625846));
#425=CARTESIAN_POINT('',(-34.4781950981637,4.9651751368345,22.5850017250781));
#426=CARTESIAN_POINT('',(-34.4209785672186,4.95298546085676,22.2821094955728));
#427=CARTESIAN_POINT('',(-34.2817747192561,4.92348679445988,21.6823260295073));
#428=CARTESIAN_POINT('',(-34.1997873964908,4.90617780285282,21.3854347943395));
#429=CARTESIAN_POINT('',(-34.0116119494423,4.86672680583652,20.7997801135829));
#430=CARTESIAN_POINT('',(-33.9054257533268,4.84458518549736,20.5110160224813));
#431=CARTESIAN_POINT('',(-33.6695763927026,4.79582854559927,19.9436331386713));
#432=CARTESIAN_POINT('',(-33.5399133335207,4.76921354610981,19.6650143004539));
#433=CARTESIAN_POINT('',(-33.2578321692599,4.71190410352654,19.1195687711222));
#434=CARTESIAN_POINT('',(-33.1053878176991,4.68120495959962,18.8527561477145));
#435=CARTESIAN_POINT('',(-32.7788934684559,4.61623623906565,18.3331441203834));
#436=CARTESIAN_POINT('',(-32.6048429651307,4.58196657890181,18.0803450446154));
#437=CARTESIAN_POINT('',(-32.2363296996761,4.5103897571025,17.5905487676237));
#438=CARTESIAN_POINT('',(-32.0418667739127,4.47308257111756,17.3535516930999));
#439=CARTESIAN_POINT('',(-31.633867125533,4.39599896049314,16.8970435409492));
#440=CARTESIAN_POINT('',(-31.4203320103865,4.3562227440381,16.6775309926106));
#441=CARTESIAN_POINT('',(-31.0011481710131,4.27945832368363,16.2816097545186));
#442=CARTESIAN_POINT('',(-30.797399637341,4.24267293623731,16.103144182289));
#443=CARTESIAN_POINT('',(-30.377205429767,4.16804353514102,15.7621159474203));
#444=CARTESIAN_POINT('',(-30.1607608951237,4.13019961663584,15.5995518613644));
#445=CARTESIAN_POINT('',(-29.7163820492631,4.05387450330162,15.2912603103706));
#446=CARTESIAN_POINT('',(-29.4884504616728,4.01539346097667,15.1455288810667));
#447=CARTESIAN_POINT('',(-29.0222683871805,3.93818298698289,14.871631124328));
#448=CARTESIAN_POINT('',(-28.7840165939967,3.89945352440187,14.7434670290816));
#449=CARTESIAN_POINT('',(-28.5412428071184,3.86080360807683,14.6244916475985));
#450=B_SPLINE_CURVE_WITH_KNOTS('',3,(#368,#369,#370,#371,#372,#373,#374,#375,#376,#377,#378,
#379,#380,#381,#382,#383,#384,#385,#386,#387,#388,#389,#390,#391,#392,#393,#394,#395,#396,#397,
#398,#399,#400,#401,#402,#403,#404,#405,#406,#407,#408,#409,#410,#411,#412,#413,#414,#415,#416,
#417,#418,#419,#420,#421,#422,#423,#424,#425,#426,#427,#428,#429,#430,#431,#432,#433,#434,#435,
#436,#437,#438,#439,#440,#441,#442,#443,#444,#445,#446,#447,#448,#449),.UNSPECIFIED.,.F.,.F.,(4,
2,2,2,2,2,2,2,2,2,2,2,2,2,2,2,2,2,2,2,2,2,2,2,2,2,2,2,2,2,2,2,2,2,2,2,2,2,2,2,4),(0.,
0.92851320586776,1.85701780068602,2.78509470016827,3.7131504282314,4.64183578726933,
5.57051695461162,6.49892327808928,7.42732129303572,8.35127181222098,9.27522128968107,
10.1993303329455,11.1234392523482,12.0461850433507,12.9689295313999,13.8916198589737,
14.8143126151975,15.7397117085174,16.6651124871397,17.5905476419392,18.5159833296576,
19.4430516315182,20.3701212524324,21.2971619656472,22.2242010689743,23.1499208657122,
24.0756400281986,25.0013959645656,25.9271509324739,26.8515250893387,27.7758994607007,
28.7002002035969,29.6244967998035,30.5498666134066,31.4752580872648,32.4006569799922,
33.3259779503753,34.1452666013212,34.9644818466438,35.7835037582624,36.6026296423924),.UNSPECIFIED.);
#451=EDGE_CURVE('E325',#365,#203,#450,.T.);
#452=ORIENTED_EDGE('',*,*,#451,.T.);
#453=ORIENTED_EDGE('',*,*,#204,.F.);
#454=EDGE_LOOP('',(#358,#367,#452,#453));
#455=FACE_BOUND('',#454,.T.);
#456=ADVANCED_FACE('F338',(#455),#271,.T.);
#457=CARTESIAN_POINT('',(17.2511916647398,2.6259922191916,33.3242100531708));
#458=CARTESIAN_POINT('',(17.4993781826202,2.64089075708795,33.5086851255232));
#459=CARTESIAN_POINT('',(17.7552628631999,2.65706460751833,33.6826969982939));
#460=CARTESIAN_POINT('',(18.28053769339,2.69210530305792,34.0086627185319));
#461=CARTESIAN_POINT('',(18.5499277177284,2.71097212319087,34.1606167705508));
#462=CARTESIAN_POINT('',(19.1002002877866,2.75153205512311,34.4412740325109));
#463=CARTESIAN_POINT('',(19.3810774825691,2.77322386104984,34.5699879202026));
#464=CARTESIAN_POINT('',(19.952432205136,2.81952002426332,34.8033129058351));
#465=CARTESIAN_POINT('',(20.2429095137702,2.84412431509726,34.9079245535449));
#466=CARTESIAN_POINT('',(20.8315983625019,2.89628797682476,35.0923323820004));
#467=CARTESIAN_POINT('',(21.1298150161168,2.92384934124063,35.1721116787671));
#468=CARTESIAN_POINT('',(21.7316508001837,2.98187199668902,35.3061577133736));
#469=CARTESIAN_POINT('',(22.035269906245,3.01233327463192,35.3604245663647));
#470=CARTESIAN_POINT('',(22.6456357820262,3.07603596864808,35.4430189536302));
#471=CARTESIAN_POINT('',(22.9523815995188,3.10927655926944,35.4713541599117));
#472=CARTESIAN_POINT('',(23.566877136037,3.17836345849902,35.501889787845));
#473=CARTESIAN_POINT('',(23.874626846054,3.21420974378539,35.504090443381));
#474=CARTESIAN_POINT('',(24.4874432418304,3.28807700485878,35.4823817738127));
#475=CARTESIAN_POINT('',(24.7925157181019,3.32608674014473,35.4585974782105));
#476=CARTESIAN_POINT('',(25.3992908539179,3.40411737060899,35.3852808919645));
#477=CARTESIAN_POINT('',(25.7009935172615,3.44413826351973,35.3357486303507));
#478=CARTESIAN_POINT('',(26.2989412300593,3.52581537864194,35.211278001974));
#479=CARTESIAN_POINT('',(26.595185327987,3.56747188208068,35.1363352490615));
#480=CARTESIAN_POINT('',(27.1800717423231,3.65197221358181,34.9615826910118));
#481=CARTESIAN_POINT('',(27.4687140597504,3.69481604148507,34.8617728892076));
#482=CARTESIAN_POINT('',(28.035952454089,3.78113479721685,34.6381665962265));
#483=CARTESIAN_POINT('',(28.3145627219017,3.82460870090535,34.514405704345));
#484=CARTESIAN_POINT('',(28.8602471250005,3.91171735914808,34.2436848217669));
#485=CARTESIAN_POINT('',(29.1273212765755,3.95535211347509,34.0967248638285));
#486=CARTESIAN_POINT('',(29.6480727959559,4.04221651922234,33.7806574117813));
#487=CARTESIAN_POINT('',(29.9017509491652,4.08544619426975,33.6115512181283));
#488=CARTESIAN_POINT('',(30.3939845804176,4.17091924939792,33.2523788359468));
#489=CARTESIAN_POINT('',(30.6325400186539,4.2131626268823,33.0623125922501));
#490=CARTESIAN_POINT('',(31.0935716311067,4.29619199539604,32.6619711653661));
#491=CARTESIAN_POINT('',(31.3159985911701,4.33697334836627,32.4516383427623));
#492=CARTESIAN_POINT('',(31.7424740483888,4.41635307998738,32.0127202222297));
#493=CARTESIAN_POINT('',(31.9465225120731,4.45495145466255,31.7841348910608));
#494=CARTESIAN_POINT('',(32.3348520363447,4.52938773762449,31.3103146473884));
#495=CARTESIAN_POINT('',(32.5191323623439,4.56522554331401,31.0650791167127));
#496=CARTESIAN_POINT('',(32.8666572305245,4.63358841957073,30.5596945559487));
#497=CARTESIAN_POINT('',(33.0299017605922,4.66611348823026,30.2995455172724));
#498=CARTESIAN_POINT('',(33.3345075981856,4.72739462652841,29.7656976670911));
#499=CARTESIAN_POINT('',(33.4758297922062,4.75614394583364,29.4919757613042));
#500=CARTESIAN_POINT('',(33.7352733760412,4.80934524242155,28.9333467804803));
#501=CARTESIAN_POINT('',(33.8533947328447,4.83379721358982,28.6484396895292));
#502=CARTESIAN_POINT('',(34.0656204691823,4.87800530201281,28.0694731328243));
#503=CARTESIAN_POINT('',(34.1597255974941,4.89776156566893,27.7754139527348));
#504=CARTESIAN_POINT('',(34.3232748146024,4.93225390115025,27.180228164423));
#505=CARTESIAN_POINT('',(34.3927189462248,4.9469899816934,26.8791015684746));
#506=CARTESIAN_POINT('',(34.5063857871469,4.97117989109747,26.2723608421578));
#507=CARTESIAN_POINT('',(34.5506442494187,4.98064120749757,25.96675370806));
#508=CARTESIAN_POINT('',(34.6137870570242,4.99415603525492,25.3528106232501));
#509=CARTESIAN_POINT('',(34.6326714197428,4.99820955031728,25.0444746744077));
#510=CARTESIAN_POINT('',(34.644935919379,5.00084099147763,24.4272603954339));
#511=CARTESIAN_POINT('',(34.6383150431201,4.99941870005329,24.1183820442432));
#512=CARTESIAN_POINT('',(34.5996125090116,4.9911218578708,23.5022985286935));
#513=CARTESIAN_POINT('',(34.5675308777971,4.9842473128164,23.1950933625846));
#514=CARTESIAN_POINT('',(34.4781950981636,4.96517513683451,22.5850017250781));
#515=CARTESIAN_POINT('',(34.4209785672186,4.95298546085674,22.2821094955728));
#516=CARTESIAN_POINT('',(34.2817747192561,4.92348679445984,21.6823260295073));
#517=CARTESIAN_POINT('',(34.1997873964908,4.90617780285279,21.3854347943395));
#518=CARTESIAN_POINT('',(34.0116119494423,4.8667268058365,20.799780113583));
#519=CARTESIAN_POINT('',(33.9054257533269,4.84458518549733,20.5110160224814));
#520=CARTESIAN_POINT('',(33.6695763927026,4.79582854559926,19.9436331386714));
#521=CARTESIAN_POINT('',(33.5399133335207,4.76921354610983,19.6650143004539));
#522=CARTESIAN_POINT('',(33.2578321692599,4.71190410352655,19.1195687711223));
#523=CARTESIAN_POINT('',(33.1053878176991,4.6812049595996,18.8527561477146));
#524=CARTESIAN_POINT('',(32.7788934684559,4.61623623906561,18.3331441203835));
#525=CARTESIAN_POINT('',(32.6048429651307,4.5819665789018,18.0803450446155));
#526=CARTESIAN_POINT('',(32.2363296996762,4.5103897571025,17.5905487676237));
#527=CARTESIAN_POINT('',(32.0418667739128,4.47308257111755,17.3535516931));
#528=CARTESIAN_POINT('',(31.6338671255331,4.39599896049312,16.8970435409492));
#529=CARTESIAN_POINT('',(31.4203320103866,4.3562227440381,16.6775309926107));
#530=CARTESIAN_POINT('',(31.0011481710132,4.27945832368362,16.2816097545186));
#531=CARTESIAN_POINT('',(30.797399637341,4.2426729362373,16.103144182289));
#532=CARTESIAN_POINT('',(30.3772054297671,4.168043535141,15.7621159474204));
#533=CARTESIAN_POINT('',(30.1607608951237,4.13019961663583,15.5995518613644));
#534=CARTESIAN_POINT('',(29.7163820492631,4.05387450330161,15.2912603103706));
#535=CARTESIAN_POINT('',(29.4884504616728,4.01539346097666,15.1455288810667));
#536=CARTESIAN_POINT('',(29.0222683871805,3.93818298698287,14.871631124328));
#537=CARTESIAN_POINT('',(28.7840165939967,3.89945352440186,14.7434670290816));
#538=CARTESIAN_POINT('',(28.5412428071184,3.86080360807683,14.6244916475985));
#539=B_SPLINE_CURVE_WITH_KNOTS('',3,(#457,#458,#459,#460,#461,#462,#463,#464,#465,#466,#467,
#468,#469,#470,#471,#472,#473,#474,#475,#476,#477,#478,#479,#480,#481,#482,#483,#484,#485,#486,
#487,#488,#489,#490,#491,#492,#493,#494,#495,#496,#497,#498,#499,#500,#501,#502,#503,#504,#505,
#506,#507,#508,#509,#510,#511,#512,#513,#514,#515,#516,#517,#518,#519,#520,#521,#522,#523,#524,
#525,#526,#527,#528,#529,#530,#531,#532,#533,#534,#535,#536,#537,#538),.UNSPECIFIED.,.F.,.F.,(4,
2,2,2,2,2,2,2,2,2,2,2,2,2,2,2,2,2,2,2,2,2,2,2,2,2,2,2,2,2,2,2,2,2,2,2,2,2,2,2,4),(0.,
0.928513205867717,1.85701780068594,2.78509470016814,3.71315042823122,4.64183578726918,
5.57051695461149,6.49892327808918,7.42732129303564,8.3512718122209,9.27522128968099,
10.1993303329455,11.1234392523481,12.0461850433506,12.9689295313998,13.8916198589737,
14.8143126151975,15.7397117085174,16.6651124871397,17.5905476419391,18.5159833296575,
19.4430516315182,20.3701212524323,21.2971619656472,22.2242010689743,23.1499208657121,
24.0756400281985,25.0013959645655,25.9271509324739,26.8515250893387,27.7758994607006,
28.7002002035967,29.6244967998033,30.5498666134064,31.4752580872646,32.400656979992,
33.3259779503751,34.145266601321,34.9644818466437,35.7835037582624,36.6026296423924),.UNSPECIFIED.);
#540=CARTESIAN_POINT('',(20.5453214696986,2.87092129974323,35.0026521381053));
#541=VERTEX_POINT('',#540);
#542=CARTESIAN_POINT('',(28.5416508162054,3.86086857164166,14.6246916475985));
#543=VERTEX_POINT('',#542);
#544=EDGE_CURVE('E408',#541,#543,#539,.T.);
#545=ORIENTED_EDGE('',*,*,#544,.F.);
#546=CARTESIAN_POINT('',(20.5453214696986,-2.87092129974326,35.0026521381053));
#547=VERTEX_POINT('',#546);
#548=EDGE_CURVE('E510',#541,#547,#363,.T.);
#549=ORIENTED_EDGE('',*,*,#548,.T.);
#550=CARTESIAN_POINT('',(17.2511916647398,-2.62599221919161,33.3242100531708));
#551=CARTESIAN_POINT('',(17.4993781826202,-2.64089075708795,33.5086851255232));
#552=CARTESIAN_POINT('',(17.7552628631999,-2.65706460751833,33.6826969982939));
#553=CARTESIAN_POINT('',(18.28053769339,-2.69210530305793,34.0086627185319));
#554=CARTESIAN_POINT('',(18.5499277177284,-2.71097212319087,34.1606167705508));
#555=CARTESIAN_POINT('',(19.1002002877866,-2.75153205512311,34.4412740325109));
#556=CARTESIAN_POINT('',(19.3810774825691,-2.77322386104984,34.5699879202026));
#557=CARTESIAN_POINT('',(19.952432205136,-2.81952002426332,34.8033129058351));
#558=CARTESIAN_POINT('',(20.2429095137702,-2.84412431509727,34.9079245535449));
#559=CARTESIAN_POINT('',(20.8315983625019,-2.89628797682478,35.0923323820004));
#560=CARTESIAN_POINT('',(21.1298150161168,-2.92384934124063,35.1721116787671));
#561=CARTESIAN_POINT('',(21.7316508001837,-2.98187199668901,35.3061577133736));
#562=CARTESIAN_POINT('',(22.035269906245,-3.01233327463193,35.3604245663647));
#563=CARTESIAN_POINT('',(22.6456357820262,-3.07603596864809,35.4430189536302));
#564=CARTESIAN_POINT('',(22.9523815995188,-3.10927655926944,35.4713541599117));
#565=CARTESIAN_POINT('',(23.566877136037,-3.17836345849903,35.501889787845));
#566=CARTESIAN_POINT('',(23.874626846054,-3.21420974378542,35.504090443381));
#567=CARTESIAN_POINT('',(24.4874432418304,-3.2880770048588,35.4823817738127));
#568=CARTESIAN_POINT('',(24.7925157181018,-3.32608674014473,35.4585974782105));
#569=CARTESIAN_POINT('',(25.3992908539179,-3.40411737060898,35.3852808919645));
#570=CARTESIAN_POINT('',(25.7009935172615,-3.44413826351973,35.3357486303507));
#571=CARTESIAN_POINT('',(26.2989412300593,-3.52581537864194,35.211278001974));
#572=CARTESIAN_POINT('',(26.595185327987,-3.56747188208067,35.1363352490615));
#573=CARTESIAN_POINT('',(27.1800717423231,-3.65197221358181,34.9615826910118));
#574=CARTESIAN_POINT('',(27.4687140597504,-3.69481604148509,34.8617728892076));
#575=CARTESIAN_POINT('',(28.035952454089,-3.78113479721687,34.6381665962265));
#576=CARTESIAN_POINT('',(28.3145627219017,-3.82460870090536,34.514405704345));
#577=CARTESIAN_POINT('',(28.8602471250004,-3.91171735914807,34.2436848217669));
#578=CARTESIAN_POINT('',(29.1273212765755,-3.95535211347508,34.0967248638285));
#579=CARTESIAN_POINT('',(29.6480727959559,-4.04221651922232,33.7806574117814));
#580=CARTESIAN_POINT('',(29.9017509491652,-4.08544619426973,33.6115512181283));
#581=CARTESIAN_POINT('',(30.3939845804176,-4.17091924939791,33.2523788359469));
#582=CARTESIAN_POINT('',(30.6325400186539,-4.21316262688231,33.0623125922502));
#583=CARTESIAN_POINT('',(31.0935716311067,-4.29619199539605,32.6619711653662));
#584=CARTESIAN_POINT('',(31.3159985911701,-4.33697334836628,32.4516383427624));
#585=CARTESIAN_POINT('',(31.7424740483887,-4.41635307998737,32.0127202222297));
#586=CARTESIAN_POINT('',(31.9465225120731,-4.45495145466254,31.7841348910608));
#587=CARTESIAN_POINT('',(32.3348520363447,-4.52938773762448,31.3103146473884));
#588=CARTESIAN_POINT('',(32.5191323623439,-4.56522554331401,31.0650791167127));
#589=CARTESIAN_POINT('',(32.8666572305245,-4.63358841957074,30.5596945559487));
#590=CARTESIAN_POINT('',(33.0299017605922,-4.66611348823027,30.2995455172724));
#591=CARTESIAN_POINT('',(33.3345075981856,-4.72739462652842,29.7656976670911));
#592=CARTESIAN_POINT('',(33.4758297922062,-4.75614394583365,29.4919757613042));
#593=CARTESIAN_POINT('',(33.7352733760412,-4.80934524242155,28.9333467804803));
#594=CARTESIAN_POINT('',(33.8533947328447,-4.83379721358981,28.6484396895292));
#595=CARTESIAN_POINT('',(34.0656204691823,-4.87800530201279,28.0694731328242));
#596=CARTESIAN_POINT('',(34.1597255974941,-4.89776156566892,27.7754139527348));
#597=CARTESIAN_POINT('',(34.3232748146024,-4.93225390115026,27.180228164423));
#598=CARTESIAN_POINT('',(34.3927189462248,-4.94698998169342,26.8791015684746));
#599=CARTESIAN_POINT('',(34.5063857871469,-4.9711798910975,26.2723608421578));
#600=CARTESIAN_POINT('',(34.5506442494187,-4.98064120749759,25.96675370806));
#601=CARTESIAN_POINT('',(34.6137870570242,-4.99415603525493,25.3528106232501));
#602=CARTESIAN_POINT('',(34.6326714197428,-4.99820955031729,25.0444746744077));
#603=CARTESIAN_POINT('',(34.644935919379,-5.00084099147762,24.4272603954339));
#604=CARTESIAN_POINT('',(34.6383150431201,-4.99941870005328,24.1183820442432));
#605=CARTESIAN_POINT('',(34.5996125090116,-4.99112185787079,23.5022985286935));
#606=CARTESIAN_POINT('',(34.5675308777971,-4.98424731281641,23.1950933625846));
#607=CARTESIAN_POINT('',(34.4781950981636,-4.96517513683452,22.5850017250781));
#608=CARTESIAN_POINT('',(34.4209785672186,-4.95298546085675,22.2821094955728));
#609=CARTESIAN_POINT('',(34.2817747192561,-4.92348679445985,21.6823260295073));
#610=CARTESIAN_POINT('',(34.1997873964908,-4.9061778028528,21.3854347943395));
#611=CARTESIAN_POINT('',(34.0116119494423,-4.8667268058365,20.799780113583));
#612=CARTESIAN_POINT('',(33.9054257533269,-4.84458518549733,20.5110160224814));
#613=CARTESIAN_POINT('',(33.6695763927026,-4.79582854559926,19.9436331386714));
#614=CARTESIAN_POINT('',(33.5399133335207,-4.76921354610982,19.6650143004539));
#615=CARTESIAN_POINT('',(33.2578321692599,-4.71190410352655,19.1195687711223));
#616=CARTESIAN_POINT('',(33.1053878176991,-4.68120495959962,18.8527561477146));
#617=CARTESIAN_POINT('',(32.7788934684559,-4.61623623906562,18.3331441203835));
#618=CARTESIAN_POINT('',(32.6048429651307,-4.58196657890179,18.0803450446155));
#619=CARTESIAN_POINT('',(32.2363296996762,-4.51038975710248,17.5905487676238));
#620=CARTESIAN_POINT('',(32.0418667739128,-4.47308257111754,17.3535516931));
#621=CARTESIAN_POINT('',(31.6338671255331,-4.39599896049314,16.8970435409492));
#622=CARTESIAN_POINT('',(31.4203320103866,-4.35622274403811,16.6775309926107));
#623=CARTESIAN_POINT('',(31.0011481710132,-4.27945832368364,16.2816097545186));
#624=CARTESIAN_POINT('',(30.797399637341,-4.2426729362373,16.103144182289));
#625=CARTESIAN_POINT('',(30.3772054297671,-4.16804353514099,15.7621159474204));
#626=CARTESIAN_POINT('',(30.1607608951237,-4.13019961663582,15.5995518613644));
#627=CARTESIAN_POINT('',(29.7163820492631,-4.0538745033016,15.2912603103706));
#628=CARTESIAN_POINT('',(29.4884504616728,-4.01539346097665,15.1455288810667));
#629=CARTESIAN_POINT('',(29.0222683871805,-3.93818298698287,14.871631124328));
#630=CARTESIAN_POINT('',(28.7840165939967,-3.89945352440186,14.7434670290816));
#631=CARTESIAN_POINT('',(28.5412428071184,-3.86080360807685,14.6244916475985));
#632=B_SPLINE_CURVE_WITH_KNOTS('',3,(#550,#551,#552,#553,#554,#555,#556,#557,#558,#559,#560,
#561,#562,#563,#564,#565,#566,#567,#568,#569,#570,#571,#572,#573,#574,#575,#576,#577,#578,#579,
#580,#581,#582,#583,#584,#585,#586,#587,#588,#589,#590,#591,#592,#593,#594,#595,#596,#597,#598,
#599,#600,#601,#602,#603,#604,#605,#606,#607,#608,#609,#610,#611,#612,#613,#614,#615,#616,#617,
#618,#619,#620,#621,#622,#623,#624,#625,#626,#627,#628,#629,#630,#631),.UNSPECIFIED.,.F.,.F.,(4,
2,2,2,2,2,2,2,2,2,2,2,2,2,2,2,2,2,2,2,2,2,2,2,2,2,2,2,2,2,2,2,2,2,2,2,2,2,2,2,4),(0.,
0.928513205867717,1.85701780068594,2.78509470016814,3.71315042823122,4.64183578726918,
5.5705169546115,6.49892327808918,7.42732129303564,8.35127181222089,9.27522128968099,
10.1993303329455,11.1234392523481,12.0461850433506,12.9689295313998,13.8916198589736,
14.8143126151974,15.7397117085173,16.6651124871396,17.5905476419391,18.5159833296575,
19.4430516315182,20.3701212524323,21.2971619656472,22.2242010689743,23.1499208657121,
24.0756400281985,25.0013959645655,25.9271509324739,26.8515250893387,27.7758994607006,
28.7002002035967,29.6244967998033,30.5498666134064,31.4752580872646,32.400656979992,
33.3259779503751,34.145266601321,34.9644818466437,35.7835037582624,36.6026296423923),.UNSPECIFIED.);
#633=CARTESIAN_POINT('',(28.5416508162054,-3.86086857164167,14.6246916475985));
#634=VERTEX_POINT('',#633);
#635=EDGE_CURVE('E425',#547,#634,#632,.T.);
#636=ORIENTED_EDGE('',*,*,#635,.T.);
#637=EDGE_CURVE('E512',#543,#634,#201,.T.);
#638=ORIENTED_EDGE('',*,*,#637,.F.);
#639=EDGE_LOOP('',(#545,#549,#636,#638));
#640=FACE_BOUND('',#639,.T.);
#641=ADVANCED_FACE('F561',(#640),#271,.T.);
#642=CARTESIAN_POINT('',(0.,0.,108.534563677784));
#643=DIRECTION('',(0.,0.,-1.));
#644=DIRECTION('',(0.,1.,0.));
#645=AXIS2_PLACEMENT_3D('',#642,#643,#644);
#646=DEGENERATE_TOROIDAL_SURFACE('',#645,1.14046835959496,76.7197040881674,.F.);
#647=CARTESIAN_POINT('',(-20.5459916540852,2.87098073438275,35.0028521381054));
#648=CARTESIAN_POINT('',(-20.2734455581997,2.84680929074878,34.921515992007));
#649=CARTESIAN_POINT('',(-20.0003575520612,2.82356163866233,34.8417207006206));
#650=CARTESIAN_POINT('',(-19.4531914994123,2.77894016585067,34.6852395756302));
#651=CARTESIAN_POINT('',(-19.1791136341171,2.75756601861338,34.6085532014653));
#652=CARTESIAN_POINT('',(-18.6299663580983,2.71670934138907,34.4582892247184));
#653=CARTESIAN_POINT('',(-18.3548969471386,2.69722681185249,34.3847116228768));
#654=CARTESIAN_POINT('',(-17.8037653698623,2.66017102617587,34.2406661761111));
#655=CARTESIAN_POINT('',(-17.527703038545,2.64259810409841,34.170198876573));
#656=CARTESIAN_POINT('',(-17.2511916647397,2.6259922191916,34.1013000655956));
#657=B_SPLINE_CURVE_WITH_KNOTS('',3,(#647,#648,#649,#650,#651,#652,#653,#654,#655,#656),
.UNSPECIFIED.,.F.,.F.,(4,2,2,2,4),(0.,0.856341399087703,1.71253325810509,2.5687253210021,
3.42506692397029),.UNSPECIFIED.);
#658=CARTESIAN_POINT('',(-17.2513916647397,2.62600423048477,34.101349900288));
#659=VERTEX_POINT('',#658);
#660=EDGE_CURVE('E154',#365,#659,#657,.T.);
#661=ORIENTED_EDGE('',*,*,#660,.F.);
#662=ORIENTED_EDGE('',*,*,#366,.F.);
#663=CARTESIAN_POINT('',(-20.5459916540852,-2.87098073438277,35.0028521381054));
#664=CARTESIAN_POINT('',(-20.2734455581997,-2.84680929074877,34.921515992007));
#665=CARTESIAN_POINT('',(-20.0003575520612,-2.82356163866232,34.8417207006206));
#666=CARTESIAN_POINT('',(-19.4531914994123,-2.77894016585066,34.6852395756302));
#667=CARTESIAN_POINT('',(-19.1791136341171,-2.75756601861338,34.6085532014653));
#668=CARTESIAN_POINT('',(-18.6299663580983,-2.71670934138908,34.4582892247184));
#669=CARTESIAN_POINT('',(-18.3548969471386,-2.69722681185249,34.3847116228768));
#670=CARTESIAN_POINT('',(-17.8037653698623,-2.66017102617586,34.2406661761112));
#671=CARTESIAN_POINT('',(-17.527703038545,-2.64259810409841,34.170198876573));
#672=CARTESIAN_POINT('',(-17.2511916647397,-2.62599221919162,34.1013000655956));
#673=B_SPLINE_CURVE_WITH_KNOTS('',3,(#663,#664,#665,#666,#667,#668,#669,#670,#671,#672),
.UNSPECIFIED.,.F.,.F.,(4,2,2,2,4),(0.,0.856341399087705,1.7125332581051,2.56872532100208,
3.42506692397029),.UNSPECIFIED.);
#674=CARTESIAN_POINT('',(-17.2513916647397,-2.62600423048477,34.101349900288));
#675=VERTEX_POINT('',#674);
#676=EDGE_CURVE('E265',#356,#675,#673,.T.);
#677=ORIENTED_EDGE('',*,*,#676,.T.);
#678=CARTESIAN_POINT('',(-7.87158558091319,-6.16745020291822,32.6280175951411));
#679=CARTESIAN_POINT('',(-8.10562638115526,-5.93492845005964,32.6339970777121));
#680=CARTESIAN_POINT('',(-8.34903750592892,-5.71197629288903,32.6443415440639));
#681=CARTESIAN_POINT('',(-8.85266566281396,-5.28663541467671,32.6735423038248));
#682=CARTESIAN_POINT('',(-9.11287993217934,-5.08424332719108,32.6923972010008));
#683=CARTESIAN_POINT('',(-9.64768566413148,-4.70177870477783,32.7383536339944));
#684=CARTESIAN_POINT('',(-9.9222452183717,-4.52165940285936,32.7654374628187));
#685=CARTESIAN_POINT('',(-10.4842397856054,-4.18434626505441,32.8275519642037));
#686=CARTESIAN_POINT('',(-10.7716748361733,-4.02715249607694,32.8625826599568));
#687=CARTESIAN_POINT('',(-11.3586709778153,-3.73594391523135,32.9404074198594));
#688=CARTESIAN_POINT('',(-11.6582807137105,-3.6020363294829,32.9832356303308));
#689=CARTESIAN_POINT('',(-12.2662817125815,-3.35895829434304,33.0761486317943));
#690=CARTESIAN_POINT('',(-12.5746732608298,-3.24978864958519,33.1262336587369));
#691=CARTESIAN_POINT('',(-13.1980910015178,-3.05667738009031,33.2332336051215));
#692=CARTESIAN_POINT('',(-13.5131170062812,-2.97273504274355,33.2901483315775));
#693=CARTESIAN_POINT('',(-14.147567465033,-2.83037149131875,33.4103380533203));
#694=CARTESIAN_POINT('',(-14.4669909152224,-2.77194454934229,33.4736116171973));
#695=CARTESIAN_POINT('',(-15.1975932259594,-2.66797952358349,33.624536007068));
#696=CARTESIAN_POINT('',(-15.6095783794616,-2.63054814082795,33.7140717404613));
#697=CARTESIAN_POINT('',(-16.2267522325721,-2.60562485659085,33.8547544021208));
#698=CARTESIAN_POINT('',(-16.4321849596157,-2.60251147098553,33.9026724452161));
#699=CARTESIAN_POINT('',(-16.8424441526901,-2.60657142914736,34.0005392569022));
#700=CARTESIAN_POINT('',(-17.0472706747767,-2.61374378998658,34.0504878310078));
#701=CARTESIAN_POINT('',(-17.2515916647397,-2.62601624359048,34.1013997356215));
#702=B_SPLINE_CURVE_WITH_KNOTS('',3,(#678,#679,#680,#681,#682,#683,#684,#685,#686,#687,#688,
#689,#690,#691,#692,#693,#694,#695,#696,#697,#698,#699,#700,#701),.UNSPECIFIED.,.F.,.F.,(4,2,2,
2,2,2,2,2,2,2,2,4),(0.,0.989573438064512,1.97898458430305,2.96628161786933,3.9535815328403,
4.94531376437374,5.93707824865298,6.92881471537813,7.92032843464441,9.18766059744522,
9.8203528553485,10.4529846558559),.UNSPECIFIED.);
#703=CARTESIAN_POINT('',(-7.8717855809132,-6.16725155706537,32.6280227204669));
#704=VERTEX_POINT('',#703);
#705=EDGE_CURVE('E459',#704,#675,#702,.T.);
#706=ORIENTED_EDGE('',*,*,#705,.F.);
#707=CARTESIAN_POINT('',(0.,0.,32.6280227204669));
#708=DIRECTION('',(0.,0.,1.));
#709=DIRECTION('',(0.,-1.,0.));
#710=AXIS2_PLACEMENT_3D('',#707,#708,#709);
#711=CIRCLE('',#710,10.);
#712=CARTESIAN_POINT('',(7.8717855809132,-6.16725155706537,32.6280227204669));
#713=VERTEX_POINT('',#712);
#714=EDGE_CURVE('E456',#713,#704,#711,.F.);
#715=ORIENTED_EDGE('',*,*,#714,.F.);
#716=CARTESIAN_POINT('',(7.87158558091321,-6.16745020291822,32.6280175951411));
#717=CARTESIAN_POINT('',(8.1056263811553,-5.93492845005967,32.6339970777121));
#718=CARTESIAN_POINT('',(8.34903750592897,-5.71197629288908,32.6443415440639));
#719=CARTESIAN_POINT('',(8.85266566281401,-5.28663541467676,32.6735423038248));
#720=CARTESIAN_POINT('',(9.11287993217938,-5.08424332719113,32.6923972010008));
#721=CARTESIAN_POINT('',(9.64768566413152,-4.70177870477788,32.7383536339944));
#722=CARTESIAN_POINT('',(9.92224521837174,-4.52165940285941,32.7654374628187));
#723=CARTESIAN_POINT('',(10.4842397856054,-4.18434626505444,32.8275519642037));
#724=CARTESIAN_POINT('',(10.7716748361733,-4.02715249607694,32.8625826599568));
#725=CARTESIAN_POINT('',(11.3586709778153,-3.73594391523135,32.9404074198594));
#726=CARTESIAN_POINT('',(11.6582807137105,-3.60203632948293,32.9832356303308));
#727=CARTESIAN_POINT('',(12.2662817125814,-3.3589582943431,33.0761486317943));
#728=CARTESIAN_POINT('',(12.5746732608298,-3.24978864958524,33.1262336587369));
#729=CARTESIAN_POINT('',(13.1980910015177,-3.05667738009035,33.2332336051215));
#730=CARTESIAN_POINT('',(13.5131170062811,-2.9727350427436,33.2901483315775));
#731=CARTESIAN_POINT('',(14.1475674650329,-2.83037149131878,33.4103380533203));
#732=CARTESIAN_POINT('',(14.4669909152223,-2.7719445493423,33.4736116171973));
#733=CARTESIAN_POINT('',(15.1975932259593,-2.66797952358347,33.624536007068));
#734=CARTESIAN_POINT('',(15.6095783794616,-2.63054814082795,33.7140717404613));
#735=CARTESIAN_POINT('',(16.2267522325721,-2.60562485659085,33.8547544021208));
#736=CARTESIAN_POINT('',(16.4321849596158,-2.60251147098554,33.9026724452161));
#737=CARTESIAN_POINT('',(16.8424441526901,-2.60657142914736,34.0005392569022));
#738=CARTESIAN_POINT('',(17.0472706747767,-2.61374378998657,34.0504878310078));
#739=CARTESIAN_POINT('',(17.2515916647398,-2.62601624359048,34.1013997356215));
#740=B_SPLINE_CURVE_WITH_KNOTS('',3,(#716,#717,#718,#719,#720,#721,#722,#723,#724,#725,#726,
#727,#728,#729,#730,#731,#732,#733,#734,#735,#736,#737,#738,#739),.UNSPECIFIED.,.F.,.F.,(4,2,2,
2,2,2,2,2,2,2,2,4),(0.,0.989573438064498,1.97898458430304,2.9662816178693,3.95358153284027,
4.94531376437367,5.93707824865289,6.92881471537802,7.92032843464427,9.18766059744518,
9.82035285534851,10.452984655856),.UNSPECIFIED.);
#741=CARTESIAN_POINT('',(17.2513916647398,-2.62600423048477,34.101349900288));
#742=VERTEX_POINT('',#741);
#743=EDGE_CURVE('E204',#713,#742,#740,.T.);
#744=ORIENTED_EDGE('',*,*,#743,.T.);
#745=CARTESIAN_POINT('',(20.5459916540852,-2.87098073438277,35.0028521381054));
#746=CARTESIAN_POINT('',(20.2734455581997,-2.84680929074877,34.9215159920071));
#747=CARTESIAN_POINT('',(20.0003575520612,-2.82356163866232,34.8417207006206));
#748=CARTESIAN_POINT('',(19.4531914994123,-2.77894016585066,34.6852395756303));
#749=CARTESIAN_POINT('',(19.1791136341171,-2.75756601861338,34.6085532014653));
#750=CARTESIAN_POINT('',(18.6299663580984,-2.71670934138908,34.4582892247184));
#751=CARTESIAN_POINT('',(18.3548969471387,-2.6972268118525,34.3847116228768));
#752=CARTESIAN_POINT('',(17.8037653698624,-2.66017102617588,34.2406661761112));
#753=CARTESIAN_POINT('',(17.527703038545,-2.64259810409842,34.170198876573));
#754=CARTESIAN_POINT('',(17.2511916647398,-2.62599221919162,34.1013000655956));
#755=B_SPLINE_CURVE_WITH_KNOTS('',3,(#745,#746,#747,#748,#749,#750,#751,#752,#753,#754),
.UNSPECIFIED.,.F.,.F.,(4,2,2,2,4),(0.,0.856341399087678,1.71253325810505,2.56872532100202,
3.42506692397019),.UNSPECIFIED.);
#756=EDGE_CURVE('E453',#547,#742,#755,.T.);
#757=ORIENTED_EDGE('',*,*,#756,.F.);
#758=ORIENTED_EDGE('',*,*,#548,.F.);
#759=CARTESIAN_POINT('',(20.5459916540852,2.87098073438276,35.0028521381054));
#760=CARTESIAN_POINT('',(20.2734455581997,2.84680929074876,34.9215159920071));
#761=CARTESIAN_POINT('',(20.0003575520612,2.82356163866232,34.8417207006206));
#762=CARTESIAN_POINT('',(19.4531914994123,2.77894016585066,34.6852395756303));
#763=CARTESIAN_POINT('',(19.1791136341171,2.75756601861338,34.6085532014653));
#764=CARTESIAN_POINT('',(18.6299663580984,2.71670934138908,34.4582892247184));
#765=CARTESIAN_POINT('',(18.3548969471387,2.6972268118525,34.3847116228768));
#766=CARTESIAN_POINT('',(17.8037653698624,2.66017102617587,34.2406661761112));
#767=CARTESIAN_POINT('',(17.527703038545,2.64259810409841,34.170198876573));
#768=CARTESIAN_POINT('',(17.2511916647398,2.6259922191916,34.1013000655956));
#769=B_SPLINE_CURVE_WITH_KNOTS('',3,(#759,#760,#761,#762,#763,#764,#765,#766,#767,#768),
.UNSPECIFIED.,.F.,.F.,(4,2,2,2,4),(0.,0.856341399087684,1.71253325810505,2.56872532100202,
3.42506692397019),.UNSPECIFIED.);
#770=CARTESIAN_POINT('',(17.2513916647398,2.62600423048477,34.101349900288));
#771=VERTEX_POINT('',#770);
#772=EDGE_CURVE('E261',#541,#771,#769,.T.);
#773=ORIENTED_EDGE('',*,*,#772,.T.);
#774=CARTESIAN_POINT('',(7.87158558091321,6.16745020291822,32.6280175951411));
#775=CARTESIAN_POINT('',(8.1056263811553,5.93492845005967,32.6339970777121));
#776=CARTESIAN_POINT('',(8.34903750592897,5.71197629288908,32.6443415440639));
#777=CARTESIAN_POINT('',(8.85266566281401,5.28663541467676,32.6735423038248));
#778=CARTESIAN_POINT('',(9.11287993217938,5.08424332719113,32.6923972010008));
#779=CARTESIAN_POINT('',(9.64768566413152,4.70177870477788,32.7383536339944));
#780=CARTESIAN_POINT('',(9.92224521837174,4.52165940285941,32.7654374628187));
#781=CARTESIAN_POINT('',(10.4842397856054,4.18434626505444,32.8275519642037));
#782=CARTESIAN_POINT('',(10.7716748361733,4.02715249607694,32.8625826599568));
#783=CARTESIAN_POINT('',(11.3586709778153,3.73594391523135,32.9404074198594));
#784=CARTESIAN_POINT('',(11.6582807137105,3.60203632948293,32.9832356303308));
#785=CARTESIAN_POINT('',(12.2662817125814,3.3589582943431,33.0761486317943));
#786=CARTESIAN_POINT('',(12.5746732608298,3.24978864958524,33.1262336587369));
#787=CARTESIAN_POINT('',(13.1980910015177,3.05667738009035,33.2332336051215));
#788=CARTESIAN_POINT('',(13.5131170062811,2.9727350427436,33.2901483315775));
#789=CARTESIAN_POINT('',(14.1475674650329,2.83037149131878,33.4103380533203));
#790=CARTESIAN_POINT('',(14.4669909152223,2.7719445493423,33.4736116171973));
#791=CARTESIAN_POINT('',(15.1975932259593,2.66797952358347,33.624536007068));
#792=CARTESIAN_POINT('',(15.6095783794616,2.63054814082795,33.7140717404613));
#793=CARTESIAN_POINT('',(16.2267522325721,2.60562485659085,33.8547544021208));
#794=CARTESIAN_POINT('',(16.4321849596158,2.60251147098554,33.9026724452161));
#795=CARTESIAN_POINT('',(16.8424441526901,2.60657142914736,34.0005392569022));
#796=CARTESIAN_POINT('',(17.0472706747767,2.61374378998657,34.0504878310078));
#797=CARTESIAN_POINT('',(17.2515916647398,2.62601624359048,34.1013997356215));
#798=B_SPLINE_CURVE_WITH_KNOTS('',3,(#774,#775,#776,#777,#778,#779,#780,#781,#782,#783,#784,
#785,#786,#787,#788,#789,#790,#791,#792,#793,#794,#795,#796,#797),.UNSPECIFIED.,.F.,.F.,(4,2,2,
2,2,2,2,2,2,2,2,4),(0.,0.989573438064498,1.97898458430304,2.9662816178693,3.95358153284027,
4.94531376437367,5.93707824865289,6.92881471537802,7.92032843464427,9.18766059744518,
9.82035285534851,10.452984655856),.UNSPECIFIED.);
#799=CARTESIAN_POINT('',(7.8717855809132,6.16725155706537,32.6280227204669));
#800=VERTEX_POINT('',#799);
#801=EDGE_CURVE('E247',#800,#771,#798,.T.);
#802=ORIENTED_EDGE('',*,*,#801,.F.);
#803=CARTESIAN_POINT('',(0.,0.,32.6280227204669));
#804=DIRECTION('',(0.,0.,1.));
#805=DIRECTION('',(0.,-1.,0.));
#806=AXIS2_PLACEMENT_3D('',#803,#804,#805);
#807=CIRCLE('',#806,10.);
#808=CARTESIAN_POINT('',(-7.8717855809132,6.16725155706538,32.6280227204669));
#809=VERTEX_POINT('',#808);
#810=EDGE_CURVE('E258',#809,#800,#807,.F.);
#811=ORIENTED_EDGE('',*,*,#810,.F.);
#812=CARTESIAN_POINT('',(-7.87158558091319,6.1674502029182,32.6280175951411));
#813=CARTESIAN_POINT('',(-8.10562638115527,5.93492845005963,32.6339970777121));
#814=CARTESIAN_POINT('',(-8.34903750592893,5.71197629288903,32.6443415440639));
#815=CARTESIAN_POINT('',(-8.85266566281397,5.2866354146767,32.6735423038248));
#816=CARTESIAN_POINT('',(-9.11287993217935,5.08424332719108,32.6923972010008));
#817=CARTESIAN_POINT('',(-9.64768566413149,4.70177870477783,32.7383536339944));
#818=CARTESIAN_POINT('',(-9.92224521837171,4.52165940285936,32.7654374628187));
#819=CARTESIAN_POINT('',(-10.4842397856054,4.18434626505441,32.8275519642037));
#820=CARTESIAN_POINT('',(-10.7716748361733,4.02715249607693,32.8625826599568));
#821=CARTESIAN_POINT('',(-11.3586709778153,3.73594391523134,32.9404074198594));
#822=CARTESIAN_POINT('',(-11.6582807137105,3.60203632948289,32.9832356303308));
#823=CARTESIAN_POINT('',(-12.2662817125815,3.35895829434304,33.0761486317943));
#824=CARTESIAN_POINT('',(-12.5746732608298,3.24978864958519,33.1262336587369));
#825=CARTESIAN_POINT('',(-13.1980910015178,3.05667738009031,33.2332336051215));
#826=CARTESIAN_POINT('',(-13.5131170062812,2.97273504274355,33.2901483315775));
#827=CARTESIAN_POINT('',(-14.147567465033,2.83037149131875,33.4103380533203));
#828=CARTESIAN_POINT('',(-14.4669909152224,2.77194454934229,33.4736116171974));
#829=CARTESIAN_POINT('',(-15.1975932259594,2.66797952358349,33.6245360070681));
#830=CARTESIAN_POINT('',(-15.6095783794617,2.63054814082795,33.7140717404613));
#831=CARTESIAN_POINT('',(-16.2267522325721,2.60562485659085,33.8547544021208));
#832=CARTESIAN_POINT('',(-16.4321849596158,2.60251147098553,33.9026724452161));
#833=CARTESIAN_POINT('',(-16.8424441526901,2.60657142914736,34.0005392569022));
#834=CARTESIAN_POINT('',(-17.0472706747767,2.61374378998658,34.0504878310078));
#835=CARTESIAN_POINT('',(-17.2515916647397,2.62601624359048,34.1013997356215));
#836=B_SPLINE_CURVE_WITH_KNOTS('',3,(#812,#813,#814,#815,#816,#817,#818,#819,#820,#821,#822,
#823,#824,#825,#826,#827,#828,#829,#830,#831,#832,#833,#834,#835),.UNSPECIFIED.,.F.,.F.,(4,2,2,
2,2,2,2,2,2,2,2,4),(0.,0.989573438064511,1.97898458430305,2.96628161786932,3.95358153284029,
4.94531376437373,5.93707824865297,6.92881471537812,7.92032843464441,9.18766059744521,
9.82035285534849,10.4529846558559),.UNSPECIFIED.);
#837=EDGE_CURVE('E263',#809,#659,#836,.T.);
#838=ORIENTED_EDGE('',*,*,#837,.T.);
#839=EDGE_LOOP('',(#661,#662,#677,#706,#715,#744,#757,#758,#773,#802,#811,#838));
#840=FACE_BOUND('',#839,.T.);
#841=CARTESIAN_POINT('',(0.,0.,32.3029737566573));
#842=DIRECTION('',(0.,0.,-1.));
#843=DIRECTION('',(0.,1.,0.));
#844=AXIS2_PLACEMENT_3D('',#841,#842,#843);
#845=CIRCLE('',#844,7.5);
#846=CARTESIAN_POINT('',(0.,7.5,32.3029737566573));
#847=VERTEX_POINT('',#846);
#848=EDGE_CURVE('E506',#847,#847,#845,.T.);
#849=ORIENTED_EDGE('',*,*,#848,.T.);
#850=EDGE_LOOP('',(#849));
#851=FACE_BOUND('',#850,.T.);
#852=ADVANCED_FACE('F256',(#840,#851),#646,.T.);
#853=CARTESIAN_POINT('',(6.5,0.,20.));
#854=DIRECTION('',(0.,0.,1.));
#855=DIRECTION('',(0.,-1.,0.));
#856=AXIS2_PLACEMENT_3D('',#853,#854,#855);
#857=PLANE('',#856);
#858=CARTESIAN_POINT('',(0.,0.,20.));
#859=DIRECTION('',(0.,0.,-1.));
#860=DIRECTION('',(0.,1.,0.));
#861=AXIS2_PLACEMENT_3D('',#858,#859,#860);
#862=CIRCLE('',#861,5.);
#863=CARTESIAN_POINT('',(0.,5.,20.));
#864=VERTEX_POINT('',#863);
#865=EDGE_CURVE('E448',#864,#864,#862,.T.);
#866=ORIENTED_EDGE('',*,*,#865,.T.);
#867=EDGE_LOOP('',(#866));
#868=FACE_BOUND('',#867,.T.);
#869=CARTESIAN_POINT('',(0.,0.,20.));
#870=DIRECTION('',(0.,0.,-1.));
#871=DIRECTION('',(0.,1.,0.));
#872=AXIS2_PLACEMENT_3D('',#869,#870,#871);
#873=CIRCLE('',#872,6.5);
#874=CARTESIAN_POINT('',(0.,6.5,20.));
#875=VERTEX_POINT('',#874);
#876=EDGE_CURVE('E497',#875,#875,#873,.T.);
#877=ORIENTED_EDGE('',*,*,#876,.F.);
#878=EDGE_LOOP('',(#877));
#879=FACE_BOUND('',#878,.T.);
#880=ADVANCED_FACE('F16',(#868,#879),#857,.T.);
#881=CARTESIAN_POINT('',(0.,0.,-2.33088640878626));
#882=DIRECTION('',(0.,0.,-1.));
#883=DIRECTION('',(0.,1.,0.));
#884=AXIS2_PLACEMENT_3D('',#881,#882,#883);
#885=CYLINDRICAL_SURFACE('',#884,5.);
#886=CARTESIAN_POINT('',(0.,0.,0.));
#887=DIRECTION('',(0.,0.,-1.));
#888=DIRECTION('',(0.,1.,0.));
#889=AXIS2_PLACEMENT_3D('',#886,#887,#888);
#890=CIRCLE('',#889,5.);
#891=CARTESIAN_POINT('',(0.,5.,0.));
#892=VERTEX_POINT('',#891);
#893=EDGE_CURVE('E441',#892,#892,#890,.T.);
#894=ORIENTED_EDGE('',*,*,#893,.T.);
#895=EDGE_LOOP('',(#894));
#896=FACE_BOUND('',#895,.T.);
#897=ORIENTED_EDGE('',*,*,#865,.F.);
#898=EDGE_LOOP('',(#897));
#899=FACE_BOUND('',#898,.T.);
#900=ADVANCED_FACE('F583',(#896,#899),#885,.F.);
#901=CARTESIAN_POINT('',(10.,0.,0.));
#902=DIRECTION('',(0.,0.,1.));
#903=DIRECTION('',(0.,-1.,0.));
#904=AXIS2_PLACEMENT_3D('',#901,#902,#903);
#905=PLANE('',#904);
#906=ORIENTED_EDGE('',*,*,#893,.F.);
#907=EDGE_LOOP('',(#906));
#908=FACE_BOUND('',#907,.T.);
#909=CARTESIAN_POINT('',(0.,0.,0.));
#910=DIRECTION('',(0.,0.,-1.));
#911=DIRECTION('',(0.,1.,0.));
#912=AXIS2_PLACEMENT_3D('',#909,#910,#911);
#913=CIRCLE('',#912,10.);
#914=CARTESIAN_POINT('',(0.,10.,0.));
#915=VERTEX_POINT('',#914);
#916=EDGE_CURVE('E437',#915,#915,#913,.T.);
#917=ORIENTED_EDGE('',*,*,#916,.T.);
#918=EDGE_LOOP('',(#917));
#919=FACE_BOUND('',#918,.T.);
#920=ADVANCED_FACE('F589',(#908,#919),#905,.F.);
#921=CARTESIAN_POINT('',(0.,0.,-2.33088640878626));
#922=DIRECTION('',(0.,0.,-1.));
#923=DIRECTION('',(0.,1.,0.));
#924=AXIS2_PLACEMENT_3D('',#921,#922,#923);
#925=CYLINDRICAL_SURFACE('',#924,10.);
#926=ORIENTED_EDGE('',*,*,#916,.F.);
#927=EDGE_LOOP('',(#926));
#928=FACE_BOUND('',#927,.T.);
#929=DIRECTION('',(0.,0.,1.));
#930=VECTOR('',#929,1.);
#931=CARTESIAN_POINT('',(-7.8717855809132,-6.16725155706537,-6.26382242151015));
#932=LINE('',#931,#930);
#933=EDGE_CURVE('E167',#66,#704,#932,.T.);
#934=ORIENTED_EDGE('',*,*,#933,.F.);
#935=ORIENTED_EDGE('',*,*,#126,.T.);
#936=DIRECTION('',(0.,0.,1.));
#937=VECTOR('',#936,1.);
#938=CARTESIAN_POINT('',(-7.8717855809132,6.16725155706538,-6.26382242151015));
#939=LINE('',#938,#937);
#940=EDGE_CURVE('E156',#118,#809,#939,.T.);
#941=ORIENTED_EDGE('',*,*,#940,.T.);
#942=ORIENTED_EDGE('',*,*,#810,.T.);
#943=DIRECTION('',(0.,0.,1.));
#944=VECTOR('',#943,1.);
#945=CARTESIAN_POINT('',(7.8717855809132,6.16725155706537,-6.26382242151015));
#946=LINE('',#945,#944);
#947=CARTESIAN_POINT('',(7.8717855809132,6.16725155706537,8.));
#948=VERTEX_POINT('',#947);
#949=EDGE_CURVE('E160',#948,#800,#946,.T.);
#950=ORIENTED_EDGE('',*,*,#949,.F.);
#951=CARTESIAN_POINT('',(7.8717855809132,-6.16725155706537,8.));
#952=VERTEX_POINT('',#951);
#953=EDGE_CURVE('E434',#948,#952,#125,.T.);
#954=ORIENTED_EDGE('',*,*,#953,.T.);
#955=DIRECTION('',(0.,0.,1.));
#956=VECTOR('',#955,1.);
#957=CARTESIAN_POINT('',(7.8717855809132,-6.16725155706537,-6.26382242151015));
#958=LINE('',#957,#956);
#959=EDGE_CURVE('E222',#952,#713,#958,.T.);
#960=ORIENTED_EDGE('',*,*,#959,.T.);
#961=ORIENTED_EDGE('',*,*,#714,.T.);
#962=EDGE_LOOP('',(#934,#935,#941,#942,#950,#954,#960,#961));
#963=FACE_BOUND('',#962,.T.);
#964=ADVANCED_FACE('F311',(#928,#963),#925,.T.);
#965=CARTESIAN_POINT('',(10.9364004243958,3.94636818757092,9.7916319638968));
#966=CARTESIAN_POINT('',(10.8241185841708,4.00370429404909,9.78325234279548));
#967=CARTESIAN_POINT('',(10.7132133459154,4.0625440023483,9.7689718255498));
#968=CARTESIAN_POINT('',(10.4947965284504,4.18269546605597,9.73031315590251));
#969=CARTESIAN_POINT('',(10.3872790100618,4.2440024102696,9.70595387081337));
#970=CARTESIAN_POINT('',(10.1765147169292,4.36838152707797,9.64897611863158));
#971=CARTESIAN_POINT('',(10.073245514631,4.43144032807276,9.61641003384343));
#972=CARTESIAN_POINT('',(9.87034998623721,4.5594180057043,9.54423053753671));
#973=CARTESIAN_POINT('',(9.7707251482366,4.62433762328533,9.50461428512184));
#974=CARTESIAN_POINT('',(9.5507649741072,4.77218804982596,9.40879869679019));
#975=CARTESIAN_POINT('',(9.43146470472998,4.85557105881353,9.3509280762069));
#976=CARTESIAN_POINT('',(9.1984542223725,5.02453572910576,9.22749490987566));
#977=CARTESIAN_POINT('',(9.08474708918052,5.11011856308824,9.16192819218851));
#978=CARTESIAN_POINT('',(8.89583509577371,5.25740071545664,9.04459290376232));
#979=CARTESIAN_POINT('',(8.81922141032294,5.3186476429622,8.99450670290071));
#980=CARTESIAN_POINT('',(8.66877804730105,5.44185241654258,8.89113944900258));
#981=CARTESIAN_POINT('',(8.59494804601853,5.50381017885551,8.83785876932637));
#982=CARTESIAN_POINT('',(8.47417990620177,5.60755853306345,8.74594898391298));
#983=CARTESIAN_POINT('',(8.42641392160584,5.64925103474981,8.70829311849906));
#984=CARTESIAN_POINT('',(8.33242521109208,5.73256077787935,8.63109723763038));
#985=CARTESIAN_POINT('',(8.28620142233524,5.77417805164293,8.59155856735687));
#986=CARTESIAN_POINT('',(8.21125367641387,5.84266935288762,8.52388347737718));
#987=CARTESIAN_POINT('',(8.18198002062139,5.86968993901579,8.49650386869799));
#988=CARTESIAN_POINT('',(8.12444979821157,5.92330159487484,8.44010631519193));
#989=CARTESIAN_POINT('',(8.09619524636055,5.94989176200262,8.41108538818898));
#990=CARTESIAN_POINT('',(8.04234032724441,6.00103726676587,8.351790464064));
#991=CARTESIAN_POINT('',(8.01668026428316,6.02563150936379,8.32160361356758));
#992=CARTESIAN_POINT('',(7.96790958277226,6.07276025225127,8.25760239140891));
#993=CARTESIAN_POINT('',(7.9447925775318,6.09529988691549,8.22379754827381));
#994=CARTESIAN_POINT('',(7.91701322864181,6.1225563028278,8.17250880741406));
#995=CARTESIAN_POINT('',(7.90975258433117,6.12970126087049,8.15779331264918));
#996=CARTESIAN_POINT('',(7.89665438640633,6.14261741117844,8.12727584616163));
#997=CARTESIAN_POINT('',(7.89080740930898,6.14839769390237,8.11148202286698));
#998=CARTESIAN_POINT('',(7.8815822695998,6.15753000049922,8.0801327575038));
#999=CARTESIAN_POINT('',(7.87802903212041,6.16105398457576,8.06468423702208));
#1000=CARTESIAN_POINT('',(7.87307566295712,6.16597001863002,8.03281428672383));
#1001=CARTESIAN_POINT('',(7.87172008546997,6.16731795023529,8.01637956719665));
#1002=CARTESIAN_POINT('',(7.87178564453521,6.16725149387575,7.9998));
#1003=B_SPLINE_CURVE_WITH_KNOTS('',3,(#965,#966,#967,#968,#969,#970,#971,#972,#973,#974,#975,
#976,#977,#978,#979,#980,#981,#982,#983,#984,#985,#986,#987,#988,#989,#990,#991,#992,#993,#994,
#995,#996,#997,#998,#999,#1000,#1001,#1002),.UNSPECIFIED.,.F.,.F.,(4,2,2,2,2,2,2,2,2,2,2,2,2,2,
2,2,2,2,4),(0.,0.378686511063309,0.756667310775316,1.13229407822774,1.50807255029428,
1.97761636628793,2.44741590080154,2.77774393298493,3.1080334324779,3.32923096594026,
3.55027276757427,3.69527147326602,3.84054267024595,3.98039395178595,4.11988557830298,
4.17347981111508,4.22670627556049,4.2751332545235,4.3245302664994),.UNSPECIFIED.);
#1004=CARTESIAN_POINT('',(10.9337221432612,3.94773654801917,9.7914319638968));
#1005=VERTEX_POINT('',#1004);
#1006=EDGE_CURVE('E250',#1005,#948,#1003,.T.);
#1007=ORIENTED_EDGE('',*,*,#1006,.F.);
#1008=CARTESIAN_POINT('',(10.9337221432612,-3.94773654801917,9.7914319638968));
#1009=VERTEX_POINT('',#1008);
#1010=EDGE_CURVE('E407',#1005,#1009,#73,.T.);
#1011=ORIENTED_EDGE('',*,*,#1010,.T.);
#1012=CARTESIAN_POINT('',(10.936400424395,-3.94636818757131,9.79163196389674));
#1013=CARTESIAN_POINT('',(10.82411858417,-4.00370429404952,9.78325234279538));
#1014=CARTESIAN_POINT('',(10.7132133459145,-4.06254400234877,9.76897182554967));
#1015=CARTESIAN_POINT('',(10.4947965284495,-4.18269546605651,9.73031315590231));
#1016=CARTESIAN_POINT('',(10.3872790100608,-4.24400241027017,9.70595387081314));
#1017=CARTESIAN_POINT('',(10.1765147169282,-4.36838152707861,9.64897611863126));
#1018=CARTESIAN_POINT('',(10.07324551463,-4.43144032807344,9.61641003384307));
#1019=CARTESIAN_POINT('',(9.87034998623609,-4.559418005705,9.5442305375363));
#1020=CARTESIAN_POINT('',(9.77072514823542,-4.62433762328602,9.50461428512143));
#1021=CARTESIAN_POINT('',(9.55076497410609,-4.77218804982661,9.40879869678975));
#1022=CARTESIAN_POINT('',(9.431464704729,-4.85557105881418,9.35092807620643));
#1023=CARTESIAN_POINT('',(9.19845422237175,-5.02453572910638,9.2274949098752));
#1024=CARTESIAN_POINT('',(9.08474708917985,-5.11011856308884,9.1619281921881));
#1025=CARTESIAN_POINT('',(8.89583509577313,-5.25740071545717,9.04459290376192));
#1026=CARTESIAN_POINT('',(8.81922141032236,-5.31864764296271,8.9945067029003));
#1027=CARTESIAN_POINT('',(8.66877804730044,-5.44185241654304,8.89113944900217));
#1028=CARTESIAN_POINT('',(8.5949480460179,-5.50381017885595,8.83785876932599));
#1029=CARTESIAN_POINT('',(8.47417990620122,-5.60755853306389,8.74594898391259));
#1030=CARTESIAN_POINT('',(8.42641392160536,-5.64925103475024,8.70829311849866));
#1031=CARTESIAN_POINT('',(8.33242521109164,-5.73256077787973,8.63109723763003));
#1032=CARTESIAN_POINT('',(8.28620142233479,-5.77417805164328,8.59155856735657));
#1033=CARTESIAN_POINT('',(8.2112536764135,-5.84266935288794,8.52388347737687));
#1034=CARTESIAN_POINT('',(8.18198002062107,-5.86968993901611,8.49650386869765));
#1035=CARTESIAN_POINT('',(8.12444979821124,-5.92330159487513,8.44010631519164));
#1036=CARTESIAN_POINT('',(8.09619524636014,-5.94989176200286,8.41108538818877));
#1037=CARTESIAN_POINT('',(8.04234032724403,-6.00103726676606,8.35179046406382));
#1038=CARTESIAN_POINT('',(8.01668026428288,-6.02563150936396,8.32160361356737));
#1039=CARTESIAN_POINT('',(7.96790958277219,-6.07276025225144,8.25760239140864));
#1040=CARTESIAN_POINT('',(7.94479257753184,-6.09529988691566,8.22379754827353));
#1041=CARTESIAN_POINT('',(7.91701322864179,-6.12255630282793,8.17250880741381));
#1042=CARTESIAN_POINT('',(7.90975258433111,-6.12970126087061,8.15779331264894));
#1043=CARTESIAN_POINT('',(7.89665438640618,-6.14261741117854,8.12727584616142));
#1044=CARTESIAN_POINT('',(7.89080740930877,-6.14839769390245,8.11148202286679));
#1045=CARTESIAN_POINT('',(7.88158226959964,-6.15753000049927,8.08013275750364));
#1046=CARTESIAN_POINT('',(7.87802903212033,-6.1610539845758,8.06468423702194));
#1047=CARTESIAN_POINT('',(7.87307566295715,-6.16597001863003,8.03281428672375));
#1048=CARTESIAN_POINT('',(7.87172008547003,-6.1673179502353,8.0163795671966));
#1049=CARTESIAN_POINT('',(7.87178564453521,-6.16725149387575,7.9998));
#1050=B_SPLINE_CURVE_WITH_KNOTS('',3,(#1012,#1013,#1014,#1015,#1016,#1017,#1018,#1019,#1020,
#1021,#1022,#1023,#1024,#1025,#1026,#1027,#1028,#1029,#1030,#1031,#1032,#1033,#1034,#1035,#1036,
#1037,#1038,#1039,#1040,#1041,#1042,#1043,#1044,#1045,#1046,#1047,#1048,#1049),.UNSPECIFIED.,
.F.,.F.,(4,2,2,2,2,2,2,2,2,2,2,2,2,2,2,2,2,2,4),(0.,0.378686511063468,0.75666731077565,
1.1322940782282,1.50807255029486,1.97761636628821,2.44741590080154,2.77774393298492,
3.10803343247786,3.32923096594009,3.55027276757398,3.69527147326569,3.84054267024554,
3.9803939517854,4.11988557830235,4.17347981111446,4.22670627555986,4.27513325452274,
4.32453026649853),.UNSPECIFIED.);
#1051=EDGE_CURVE('E178',#1009,#952,#1050,.T.);
#1052=ORIENTED_EDGE('',*,*,#1051,.T.);
#1053=ORIENTED_EDGE('',*,*,#953,.F.);
#1054=EDGE_LOOP('',(#1007,#1011,#1052,#1053));
#1055=FACE_BOUND('',#1054,.T.);
#1056=ADVANCED_FACE('F307',(#1055),#23,.F.);
#1057=ORIENTED_EDGE('',*,*,#1010,.F.);
#1058=CARTESIAN_POINT('',(6.5467060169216,7.72330133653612,9.66697769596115));
#1059=CARTESIAN_POINT('',(6.64591288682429,7.58492422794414,9.66416255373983));
#1060=CARTESIAN_POINT('',(6.74799440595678,7.44862247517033,9.66190073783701));
#1061=CARTESIAN_POINT('',(6.95774811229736,7.18037757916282,9.65844214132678));
#1062=CARTESIAN_POINT('',(7.06542027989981,7.04843442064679,9.65724535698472));
#1063=CARTESIAN_POINT('',(7.39653737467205,6.65951022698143,9.65519040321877));
#1064=CARTESIAN_POINT('',(7.62812663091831,6.4093734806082,9.65586643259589));
#1065=CARTESIAN_POINT('',(8.11129299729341,5.92925394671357,9.66138002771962));
#1066=CARTESIAN_POINT('',(8.36287299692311,5.69927408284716,9.66621819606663));
#1067=CARTESIAN_POINT('',(8.88421895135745,5.26109545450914,9.68055080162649));
#1068=CARTESIAN_POINT('',(9.15398440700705,5.05289609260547,9.69004511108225));
#1069=CARTESIAN_POINT('',(9.70731186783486,4.66146851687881,9.71434109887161));
#1070=CARTESIAN_POINT('',(9.99073342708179,4.47803881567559,9.72909588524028));
#1071=CARTESIAN_POINT('',(10.5714417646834,4.13530031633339,9.764732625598));
#1072=CARTESIAN_POINT('',(10.8687285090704,3.97599145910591,9.78561456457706));
#1073=CARTESIAN_POINT('',(11.4746831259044,3.68269992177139,9.83420440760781));
#1074=CARTESIAN_POINT('',(11.7833407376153,3.54869504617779,9.86190627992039));
#1075=CARTESIAN_POINT('',(12.4099583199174,3.30668939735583,9.92468529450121));
#1076=CARTESIAN_POINT('',(12.7279182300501,3.19868845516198,9.95976238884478));
#1077=CARTESIAN_POINT('',(13.370278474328,3.00943594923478,10.0375625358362));
#1078=CARTESIAN_POINT('',(13.6946688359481,2.92814595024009,10.080274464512));
#1079=CARTESIAN_POINT('',(14.3479208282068,2.7924555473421,10.173495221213));
#1080=CARTESIAN_POINT('',(14.6767824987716,2.73805538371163,10.2240041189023));
#1081=CARTESIAN_POINT('',(15.3369192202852,2.65620760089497,10.3328061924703));
#1082=CARTESIAN_POINT('',(15.66819644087,2.62878831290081,10.391107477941));
#1083=CARTESIAN_POINT('',(16.3304789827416,2.60086726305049,10.5152293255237));
#1084=CARTESIAN_POINT('',(16.6614842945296,2.60036640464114,10.5810501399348));
#1085=CARTESIAN_POINT('',(17.3240428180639,2.62605289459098,10.7205107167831));
#1086=CARTESIAN_POINT('',(17.655572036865,2.65249066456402,10.7942180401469));
#1087=CARTESIAN_POINT('',(18.3138495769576,2.73187573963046,10.9484805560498));
#1088=CARTESIAN_POINT('',(18.6405974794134,2.78482535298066,11.0290363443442));
#1089=CARTESIAN_POINT('',(19.2867879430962,2.91642655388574,11.1963521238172));
#1090=CARTESIAN_POINT('',(19.6062391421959,2.99504586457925,11.2831042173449));
#1091=CARTESIAN_POINT('',(20.2362844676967,3.177089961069,11.4622866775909));
#1092=CARTESIAN_POINT('',(20.5468805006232,3.28050936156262,11.5547158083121));
#1093=CARTESIAN_POINT('',(20.8521318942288,3.39588894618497,11.6496949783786));
#1094=B_SPLINE_CURVE_WITH_KNOTS('',3,(#1058,#1059,#1060,#1061,#1062,#1063,#1064,#1065,#1066,
#1067,#1068,#1069,#1070,#1071,#1072,#1073,#1074,#1075,#1076,#1077,#1078,#1079,#1080,#1081,#1082,
#1083,#1084,#1085,#1086,#1087,#1088,#1089,#1090,#1091,#1092,#1093),.UNSPECIFIED.,.F.,.F.,(4,2,2,
2,2,2,2,2,2,2,2,2,2,2,2,2,2,4),(0.,0.510785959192,1.02157012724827,2.04291399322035,
3.06440575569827,4.0858694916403,5.09844663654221,6.11102130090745,7.12270361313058,
8.13437935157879,9.14459291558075,10.1548155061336,11.1660977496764,12.1774139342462,
13.1982178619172,14.2191106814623,15.2387247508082,16.2581176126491),.UNSPECIFIED.);
#1095=CARTESIAN_POINT('',(17.2513916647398,2.62600423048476,10.7060191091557));
#1096=VERTEX_POINT('',#1095);
#1097=EDGE_CURVE('E289',#1005,#1096,#1094,.T.);
#1098=ORIENTED_EDGE('',*,*,#1097,.T.);
#1099=CARTESIAN_POINT('',(28.542058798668,3.86093353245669,14.6248916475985));
#1100=CARTESIAN_POINT('',(28.0949251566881,3.78973654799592,14.4056959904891));
#1101=CARTESIAN_POINT('',(27.644194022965,3.7206533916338,14.1932196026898));
#1102=CARTESIAN_POINT('',(26.7359054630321,3.58698745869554,13.7818878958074));
#1103=CARTESIAN_POINT('',(26.2783480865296,3.52240464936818,13.583032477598));
#1104=CARTESIAN_POINT('',(24.8998297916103,3.33633398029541,13.0087706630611));
#1105=CARTESIAN_POINT('',(23.9692804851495,3.22192463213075,12.6538347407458));
#1106=CARTESIAN_POINT('',(22.0863023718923,3.01405683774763,12.0002442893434));
#1107=CARTESIAN_POINT('',(21.1338732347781,2.92059870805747,11.701590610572));
#1108=CARTESIAN_POINT('',(19.6898454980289,2.79722984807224,11.296179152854));
#1109=CARTESIAN_POINT('',(19.2049108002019,2.75884755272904,11.1679139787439));
#1110=CARTESIAN_POINT('',(18.2309836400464,2.68796520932,10.9259763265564));
#1111=CARTESIAN_POINT('',(17.7419911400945,2.65546521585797,10.8123039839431));
#1112=CARTESIAN_POINT('',(17.2511916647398,2.6259922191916,10.7059757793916));
#1113=B_SPLINE_CURVE_WITH_KNOTS('',3,(#1099,#1100,#1101,#1102,#1103,#1104,#1105,#1106,#1107,
#1108,#1109,#1110,#1111,#1112),.UNSPECIFIED.,.F.,.F.,(4,2,2,2,2,2,4),(0.,1.508982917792,
3.01795485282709,6.02329086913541,9.0286722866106,10.537674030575,12.0466897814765),.UNSPECIFIED.);
#1114=EDGE_CURVE('E399',#543,#1096,#1113,.T.);
#1115=ORIENTED_EDGE('',*,*,#1114,.F.);
#1116=ORIENTED_EDGE('',*,*,#637,.T.);
#1117=CARTESIAN_POINT('',(28.542058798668,-3.86093353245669,14.6248916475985));
#1118=CARTESIAN_POINT('',(28.0949251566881,-3.78973654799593,14.4056959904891));
#1119=CARTESIAN_POINT('',(27.644194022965,-3.7206533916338,14.1932196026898));
#1120=CARTESIAN_POINT('',(26.7359054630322,-3.58698745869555,13.7818878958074));
#1121=CARTESIAN_POINT('',(26.2783480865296,-3.52240464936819,13.583032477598));
#1122=CARTESIAN_POINT('',(24.8998297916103,-3.33633398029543,13.0087706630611));
#1123=CARTESIAN_POINT('',(23.9692804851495,-3.22192463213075,12.6538347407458));
#1124=CARTESIAN_POINT('',(22.0863023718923,-3.01405683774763,12.0002442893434));
#1125=CARTESIAN_POINT('',(21.1338732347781,-2.92059870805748,11.701590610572));
#1126=CARTESIAN_POINT('',(19.6898454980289,-2.79722984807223,11.296179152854));
#1127=CARTESIAN_POINT('',(19.2049108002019,-2.75884755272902,11.1679139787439));
#1128=CARTESIAN_POINT('',(18.2309836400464,-2.68796520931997,10.9259763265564));
#1129=CARTESIAN_POINT('',(17.7419911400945,-2.65546521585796,10.8123039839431));
#1130=CARTESIAN_POINT('',(17.2511916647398,-2.62599221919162,10.7059757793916));
#1131=B_SPLINE_CURVE_WITH_KNOTS('',3,(#1117,#1118,#1119,#1120,#1121,#1122,#1123,#1124,#1125,
#1126,#1127,#1128,#1129,#1130),.UNSPECIFIED.,.F.,.F.,(4,2,2,2,2,2,4),(0.,1.508982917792,
3.01795485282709,6.02329086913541,9.02867228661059,10.537674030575,12.0466897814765),.UNSPECIFIED.);
#1132=CARTESIAN_POINT('',(17.2513916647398,-2.62600423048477,10.7060191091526));
#1133=VERTEX_POINT('',#1132);
#1134=EDGE_CURVE('E409',#634,#1133,#1131,.T.);
#1135=ORIENTED_EDGE('',*,*,#1134,.T.);
#1136=CARTESIAN_POINT('',(6.5467060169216,-7.72330133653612,9.66697769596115));
#1137=CARTESIAN_POINT('',(6.64591288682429,-7.58492422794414,9.66416255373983));
#1138=CARTESIAN_POINT('',(6.74799440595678,-7.44862247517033,9.66190073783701));
#1139=CARTESIAN_POINT('',(6.95774811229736,-7.18037757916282,9.65844214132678));
#1140=CARTESIAN_POINT('',(7.06542027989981,-7.04843442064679,9.65724535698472));
#1141=CARTESIAN_POINT('',(7.39653737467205,-6.65951022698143,9.65519040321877));
#1142=CARTESIAN_POINT('',(7.62812663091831,-6.4093734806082,9.65586643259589));
#1143=CARTESIAN_POINT('',(8.11129299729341,-5.92925394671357,9.66138002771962));
#1144=CARTESIAN_POINT('',(8.36287299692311,-5.69927408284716,9.66621819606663));
#1145=CARTESIAN_POINT('',(8.88421895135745,-5.26109545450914,9.68055080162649));
#1146=CARTESIAN_POINT('',(9.15398440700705,-5.05289609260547,9.69004511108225));
#1147=CARTESIAN_POINT('',(9.70731186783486,-4.66146851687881,9.71434109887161));
#1148=CARTESIAN_POINT('',(9.99073342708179,-4.47803881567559,9.72909588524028));
#1149=CARTESIAN_POINT('',(10.5714417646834,-4.13530031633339,9.764732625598));
#1150=CARTESIAN_POINT('',(10.8687285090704,-3.97599145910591,9.78561456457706));
#1151=CARTESIAN_POINT('',(11.4746831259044,-3.68269992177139,9.83420440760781));
#1152=CARTESIAN_POINT('',(11.7833407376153,-3.54869504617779,9.86190627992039));
#1153=CARTESIAN_POINT('',(12.4099583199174,-3.30668939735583,9.92468529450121));
#1154=CARTESIAN_POINT('',(12.7279182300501,-3.19868845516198,9.95976238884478));
#1155=CARTESIAN_POINT('',(13.370278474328,-3.00943594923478,10.0375625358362));
#1156=CARTESIAN_POINT('',(13.6946688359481,-2.92814595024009,10.080274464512));
#1157=CARTESIAN_POINT('',(14.3479208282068,-2.7924555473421,10.173495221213));
#1158=CARTESIAN_POINT('',(14.6767824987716,-2.73805538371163,10.2240041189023));
#1159=CARTESIAN_POINT('',(15.3369192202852,-2.65620760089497,10.3328061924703));
#1160=CARTESIAN_POINT('',(15.66819644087,-2.62878831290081,10.391107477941));
#1161=CARTESIAN_POINT('',(16.3304789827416,-2.60086726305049,10.5152293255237));
#1162=CARTESIAN_POINT('',(16.6614842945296,-2.60036640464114,10.5810501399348));
#1163=CARTESIAN_POINT('',(17.3240428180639,-2.62605289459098,10.7205107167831));
#1164=CARTESIAN_POINT('',(17.655572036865,-2.65249066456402,10.7942180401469));
#1165=CARTESIAN_POINT('',(18.3138495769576,-2.73187573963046,10.9484805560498));
#1166=CARTESIAN_POINT('',(18.6405974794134,-2.78482535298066,11.0290363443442));
#1167=CARTESIAN_POINT('',(19.2867879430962,-2.91642655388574,11.1963521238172));
#1168=CARTESIAN_POINT('',(19.6062391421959,-2.99504586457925,11.2831042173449));
#1169=CARTESIAN_POINT('',(20.2362844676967,-3.177089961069,11.4622866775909));
#1170=CARTESIAN_POINT('',(20.5468805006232,-3.28050936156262,11.5547158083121));
#1171=CARTESIAN_POINT('',(20.8521318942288,-3.39588894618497,11.6496949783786));
#1172=B_SPLINE_CURVE_WITH_KNOTS('',3,(#1136,#1137,#1138,#1139,#1140,#1141,#1142,#1143,#1144,
#1145,#1146,#1147,#1148,#1149,#1150,#1151,#1152,#1153,#1154,#1155,#1156,#1157,#1158,#1159,#1160,
#1161,#1162,#1163,#1164,#1165,#1166,#1167,#1168,#1169,#1170,#1171),.UNSPECIFIED.,.F.,.F.,(4,2,2,
2,2,2,2,2,2,2,2,2,2,2,2,2,2,4),(0.,0.510785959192,1.02157012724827,2.04291399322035,
3.06440575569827,4.0858694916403,5.09844663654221,6.11102130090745,7.12270361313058,
8.13437935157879,9.14459291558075,10.1548155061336,11.1660977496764,12.1774139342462,
13.1982178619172,14.2191106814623,15.2387247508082,16.2581176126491),.UNSPECIFIED.);
#1173=EDGE_CURVE('E170',#1009,#1133,#1172,.T.);
#1174=ORIENTED_EDGE('',*,*,#1173,.F.);
#1175=EDGE_LOOP('',(#1057,#1098,#1115,#1116,#1135,#1174));
#1176=FACE_BOUND('',#1175,.T.);
#1177=ADVANCED_FACE('F185',(#1176),#135,.T.);
#1178=CARTESIAN_POINT('',(0.,0.,-2.33088640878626));
#1179=DIRECTION('',(0.,0.,-1.));
#1180=DIRECTION('',(0.,1.,0.));
#1181=AXIS2_PLACEMENT_3D('',#1178,#1179,#1180);
#1182=CYLINDRICAL_SURFACE('',#1181,7.5);
#1183=ORIENTED_EDGE('',*,*,#848,.F.);
#1184=EDGE_LOOP('',(#1183));
#1185=FACE_BOUND('',#1184,.T.);
#1186=CARTESIAN_POINT('',(0.,0.,22.6133806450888));
#1187=DIRECTION('',(0.,0.,-1.));
#1188=DIRECTION('',(0.,1.,0.));
#1189=AXIS2_PLACEMENT_3D('',#1186,#1187,#1188);
#1190=CIRCLE('',#1189,7.5);
#1191=CARTESIAN_POINT('',(0.,7.5,22.6133806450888));
#1192=VERTEX_POINT('',#1191);
#1193=EDGE_CURVE('E503',#1192,#1192,#1190,.T.);
#1194=ORIENTED_EDGE('',*,*,#1193,.T.);
#1195=EDGE_LOOP('',(#1194));
#1196=FACE_BOUND('',#1195,.T.);
#1197=ADVANCED_FACE('F563',(#1185,#1196),#1182,.F.);
#1198=CARTESIAN_POINT('',(6.5,0.,22.6133806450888));
#1199=DIRECTION('',(0.,0.,-1.));
#1200=DIRECTION('',(0.,1.,0.));
#1201=AXIS2_PLACEMENT_3D('',#1198,#1199,#1200);
#1202=PLANE('',#1201);
#1203=ORIENTED_EDGE('',*,*,#1193,.F.);
#1204=EDGE_LOOP('',(#1203));
#1205=FACE_BOUND('',#1204,.T.);
#1206=CARTESIAN_POINT('',(0.,0.,22.6133806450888));
#1207=DIRECTION('',(0.,0.,-1.));
#1208=DIRECTION('',(0.,1.,0.));
#1209=AXIS2_PLACEMENT_3D('',#1206,#1207,#1208);
#1210=CIRCLE('',#1209,6.5);
#1211=CARTESIAN_POINT('',(0.,6.5,22.6133806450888));
#1212=VERTEX_POINT('',#1211);
#1213=EDGE_CURVE('E500',#1212,#1212,#1210,.T.);
#1214=ORIENTED_EDGE('',*,*,#1213,.T.);
#1215=EDGE_LOOP('',(#1214));
#1216=FACE_BOUND('',#1215,.T.);
#1217=ADVANCED_FACE('F550',(#1205,#1216),#1202,.F.);
#1218=CARTESIAN_POINT('',(0.,0.,-2.33088640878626));
#1219=DIRECTION('',(0.,0.,-1.));
#1220=DIRECTION('',(0.,1.,0.));
#1221=AXIS2_PLACEMENT_3D('',#1218,#1219,#1220);
#1222=CYLINDRICAL_SURFACE('',#1221,6.5);
#1223=ORIENTED_EDGE('',*,*,#1213,.F.);
#1224=EDGE_LOOP('',(#1223));
#1225=FACE_BOUND('',#1224,.T.);
#1226=ORIENTED_EDGE('',*,*,#876,.T.);
#1227=EDGE_LOOP('',(#1226));
#1228=FACE_BOUND('',#1227,.T.);
#1229=ADVANCED_FACE('F479',(#1225,#1228),#1222,.F.);
#1230=CARTESIAN_POINT('',(-10.2946161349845,-118.46157794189,-6.26382242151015));
#1231=DIRECTION('',(0.,0.,1.));
#1232=DIRECTION('',(0.,-1.,0.));
#1233=AXIS2_PLACEMENT_3D('',#1230,#1231,#1232);
#1234=CYLINDRICAL_SURFACE('',#1233,116.044288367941);
#1235=DIRECTION('',(0.,0.,1.));
#1236=VECTOR('',#1235,1.);
#1237=CARTESIAN_POINT('',(-17.2513916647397,-2.62600423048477,-6.26382242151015));
#1238=LINE('',#1237,#1236);
#1239=CARTESIAN_POINT('',(-17.2513916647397,-2.62600423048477,21.0375722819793));
#1240=VERTEX_POINT('',#1239);
#1241=EDGE_CURVE('E164',#175,#1240,#1238,.T.);
#1242=ORIENTED_EDGE('',*,*,#1241,.T.);
#1243=CARTESIAN_POINT('',(-17.2511916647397,-2.62599221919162,21.0379050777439));
#1244=CARTESIAN_POINT('',(-17.360550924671,-2.63256021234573,20.8558730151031));
#1245=CARTESIAN_POINT('',(-17.4781769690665,-2.63977928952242,20.678886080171));
#1246=CARTESIAN_POINT('',(-17.7285891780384,-2.65558215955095,20.3361701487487));
#1247=CARTESIAN_POINT('',(-17.8613680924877,-2.66416530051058,20.1704358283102));
#1248=CARTESIAN_POINT('',(-18.1403342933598,-2.68273269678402,19.8517713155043));
#1249=CARTESIAN_POINT('',(-18.286473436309,-2.69271198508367,19.6987986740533));
#1250=CARTESIAN_POINT('',(-18.5911387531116,-2.71414613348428,19.4059031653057));
#1251=CARTESIAN_POINT('',(-18.7496661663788,-2.72560114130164,19.2659816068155));
#1252=CARTESIAN_POINT('',(-19.2412701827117,-2.76221931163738,18.8673844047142));
#1253=CARTESIAN_POINT('',(-19.5910610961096,-2.78968031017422,18.6290924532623));
#1254=CARTESIAN_POINT('',(-20.323832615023,-2.85090757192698,18.2118100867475));
#1255=CARTESIAN_POINT('',(-20.7068386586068,-2.88467869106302,18.0328656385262));
#1256=CARTESIAN_POINT('',(-21.5122385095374,-2.96001104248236,17.7306832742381));
#1257=CARTESIAN_POINT('',(-21.9356131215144,-3.00184137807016,17.6101220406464));
#1258=CARTESIAN_POINT('',(-22.7954871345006,-3.09177206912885,17.4380525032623));
#1259=CARTESIAN_POINT('',(-23.2319888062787,-3.13987351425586,17.3865562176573));
#1260=CARTESIAN_POINT('',(-24.1298090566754,-3.24404995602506,17.3524127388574));
#1261=CARTESIAN_POINT('',(-24.5912401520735,-3.30040917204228,17.3734764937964));
#1262=CARTESIAN_POINT('',(-25.5036209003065,-3.41734859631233,17.492493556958));
#1263=CARTESIAN_POINT('',(-25.9545689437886,-3.47792944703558,17.5904585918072));
#1264=CARTESIAN_POINT('',(-26.8360894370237,-3.60141943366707,17.8628288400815));
#1265=CARTESIAN_POINT('',(-27.2664963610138,-3.6643419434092,18.0377665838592));
#1266=CARTESIAN_POINT('',(-28.0897613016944,-3.7890743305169,18.4612298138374));
#1267=CARTESIAN_POINT('',(-28.4826254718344,-3.8508843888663,18.7097432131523));
#1268=CARTESIAN_POINT('',(-29.2009277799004,-3.96723220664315,19.2630368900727));
#1269=CARTESIAN_POINT('',(-29.5285296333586,-4.02196785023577,19.5649593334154));
#1270=CARTESIAN_POINT('',(-30.1237087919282,-4.12359078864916,20.2242762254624));
#1271=CARTESIAN_POINT('',(-30.3913170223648,-4.17048212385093,20.5816419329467));
#1272=CARTESIAN_POINT('',(-30.8373181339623,-4.24983645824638,21.3128397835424));
#1273=CARTESIAN_POINT('',(-31.0209063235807,-4.28311924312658,21.6834132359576));
#1274=CARTESIAN_POINT('',(-31.3188213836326,-4.33759779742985,22.4522485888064));
#1275=CARTESIAN_POINT('',(-31.4331834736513,-4.35879971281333,22.8504962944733));
#1276=CARTESIAN_POINT('',(-31.5819417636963,-4.38646265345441,23.6329821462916));
#1277=CARTESIAN_POINT('',(-31.6214051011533,-4.3938571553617,24.0162299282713));
#1278=CARTESIAN_POINT('',(-31.634312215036,-4.39627063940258,24.7838358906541));
#1279=CARTESIAN_POINT('',(-31.6077711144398,-4.39129245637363,25.16819379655));
#1280=CARTESIAN_POINT('',(-31.4916539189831,-4.36966021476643,25.9147246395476));
#1281=CARTESIAN_POINT('',(-31.4040395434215,-4.35336958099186,26.2772163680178));
#1282=CARTESIAN_POINT('',(-31.171301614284,-4.31056061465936,26.9825464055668));
#1283=CARTESIAN_POINT('',(-31.0261753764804,-4.28404180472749,27.3253837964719));
#1284=CARTESIAN_POINT('',(-30.6801290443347,-4.22174644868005,27.9896317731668));
#1285=CARTESIAN_POINT('',(-30.4781308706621,-4.18579203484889,28.3104623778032));
#1286=CARTESIAN_POINT('',(-30.026522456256,-4.10694895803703,28.9156211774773));
#1287=CARTESIAN_POINT('',(-29.7769013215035,-4.06405870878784,29.1999409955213));
#1288=CARTESIAN_POINT('',(-29.2214742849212,-3.97081569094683,29.7422665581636));
#1289=CARTESIAN_POINT('',(-28.9132096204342,-3.92017079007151,29.9977012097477));
#1290=CARTESIAN_POINT('',(-28.2607761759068,-3.81602372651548,30.4568418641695));
#1291=CARTESIAN_POINT('',(-27.9165957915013,-3.76252064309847,30.6605310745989));
#1292=CARTESIAN_POINT('',(-27.1748146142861,-3.65092338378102,31.0261640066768));
#1293=CARTESIAN_POINT('',(-26.7751452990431,-3.59278264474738,31.1838989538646));
#1294=CARTESIAN_POINT('',(-25.9555667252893,-3.47817566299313,31.4338219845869));
#1295=CARTESIAN_POINT('',(-25.535651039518,-3.42170996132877,31.5259891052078));
#1296=CARTESIAN_POINT('',(-24.6605018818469,-3.30905170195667,31.647128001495));
#1297=CARTESIAN_POINT('',(-24.2046656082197,-3.25308093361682,31.6719539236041));
#1298=CARTESIAN_POINT('',(-23.2941812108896,-3.14680042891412,31.6461183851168));
#1299=CARTESIAN_POINT('',(-22.8395332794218,-3.09649155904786,31.595445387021));
#1300=CARTESIAN_POINT('',(-22.1635402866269,-3.0256264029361,31.4625458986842));
#1301=CARTESIAN_POINT('',(-21.9367328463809,-3.00254244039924,31.4078302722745));
#1302=CARTESIAN_POINT('',(-21.4884958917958,-2.9582253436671,31.279126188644));
#1303=CARTESIAN_POINT('',(-21.2670643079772,-2.93699148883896,31.2051452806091));
#1304=CARTESIAN_POINT('',(-20.8311241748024,-2.89641504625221,31.0381373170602));
#1305=CARTESIAN_POINT('',(-20.6166214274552,-2.87707401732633,30.9450947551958));
#1306=CARTESIAN_POINT('',(-20.1965861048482,-2.84033307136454,30.7404574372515));
#1307=CARTESIAN_POINT('',(-19.9910494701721,-2.82293227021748,30.6288711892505));
#1308=CARTESIAN_POINT('',(-19.5960776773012,-2.79050166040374,30.3909216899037));
#1309=CARTESIAN_POINT('',(-19.4063577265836,-2.77542055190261,30.2650383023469));
#1310=CARTESIAN_POINT('',(-19.0388353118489,-2.74706092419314,29.9969053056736));
#1311=CARTESIAN_POINT('',(-18.8610271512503,-2.73378154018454,29.8546636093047));
#1312=CARTESIAN_POINT('',(-18.5192661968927,-2.70899133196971,29.5548548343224));
#1313=CARTESIAN_POINT('',(-18.355289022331,-2.69747736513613,29.3973158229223));
#1314=CARTESIAN_POINT('',(-18.0426182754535,-2.67613037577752,29.0677691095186));
#1315=CARTESIAN_POINT('',(-17.8939151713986,-2.66629630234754,28.8957705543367));
#1316=CARTESIAN_POINT('',(-17.6624475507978,-2.65138715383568,28.6009730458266));
#1317=CARTESIAN_POINT('',(-17.5748056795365,-2.64585026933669,28.4819960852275));
#1318=CARTESIAN_POINT('',(-17.4071874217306,-2.6354357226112,28.238951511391));
#1319=CARTESIAN_POINT('',(-17.3272016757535,-2.63055725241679,28.1148903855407));
#1320=CARTESIAN_POINT('',(-17.2511916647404,-2.62599221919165,27.988395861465));
#1321=B_SPLINE_CURVE_WITH_KNOTS('',3,(#1243,#1244,#1245,#1246,#1247,#1248,#1249,#1250,#1251,
#1252,#1253,#1254,#1255,#1256,#1257,#1258,#1259,#1260,#1261,#1262,#1263,#1264,#1265,#1266,#1267,
#1268,#1269,#1270,#1271,#1272,#1273,#1274,#1275,#1276,#1277,#1278,#1279,#1280,#1281,#1282,#1283,
#1284,#1285,#1286,#1287,#1288,#1289,#1290,#1291,#1292,#1293,#1294,#1295,#1296,#1297,#1298,#1299,
#1300,#1301,#1302,#1303,#1304,#1305,#1306,#1307,#1308,#1309,#1310,#1311,#1312,#1313,#1314,#1315,
#1316,#1317,#1318,#1319,#1320),.UNSPECIFIED.,.F.,.F.,(4,2,2,2,2,2,2,2,2,2,2,2,2,2,2,2,2,2,2,2,2,
2,2,2,2,2,2,2,2,2,2,2,2,2,2,2,2,2,4),(0.,0.63708187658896,1.27386019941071,1.90842811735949,
2.54305960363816,3.80922160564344,5.07636201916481,6.39710448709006,7.71807675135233,
9.10758912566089,10.4973134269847,11.896807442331,13.2960716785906,14.6355489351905,
15.9743341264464,17.2124522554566,18.4499399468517,19.6002244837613,20.750245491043,
21.8649336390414,22.9796738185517,24.117160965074,25.2549086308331,26.4603303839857,
27.6661428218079,28.9612559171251,30.2567828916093,31.6304309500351,33.0042889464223,
33.7069364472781,34.4093090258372,35.1122552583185,35.8148798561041,36.4985491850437,
37.1818891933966,37.8639982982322,38.5456791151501,38.989039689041,39.4318511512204),.UNSPECIFIED.);
#1322=CARTESIAN_POINT('',(-17.2513916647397,-2.62600423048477,27.9887286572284));
#1323=VERTEX_POINT('',#1322);
#1324=EDGE_CURVE('E40',#1240,#1323,#1321,.T.);
#1325=ORIENTED_EDGE('',*,*,#1324,.T.);
#1326=EDGE_CURVE('E158',#1323,#675,#1238,.T.);
#1327=ORIENTED_EDGE('',*,*,#1326,.T.);
#1328=ORIENTED_EDGE('',*,*,#676,.F.);
#1329=ORIENTED_EDGE('',*,*,#357,.T.);
#1330=ORIENTED_EDGE('',*,*,#195,.T.);
#1331=EDGE_LOOP('',(#1242,#1325,#1327,#1328,#1329,#1330));
#1332=FACE_BOUND('',#1331,.T.);
#1333=ADVANCED_FACE('F343',(#1332),#1234,.F.);
#1334=CARTESIAN_POINT('',(-16.5160135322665,-14.8706062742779,-6.26382242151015));
#1335=DIRECTION('',(0.,0.,1.));
#1336=DIRECTION('',(0.,-1.,0.));
#1337=AXIS2_PLACEMENT_3D('',#1334,#1335,#1336);
#1338=CYLINDRICAL_SURFACE('',#1337,12.2666645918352);
#1339=CARTESIAN_POINT('',(-17.2515916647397,-2.62601624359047,21.0372395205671));
#1340=CARTESIAN_POINT('',(-17.1553838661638,-2.62022150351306,21.1974244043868));
#1341=CARTESIAN_POINT('',(-17.0632330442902,-2.61583941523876,21.3600342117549));
#1342=CARTESIAN_POINT('',(-16.888739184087,-2.60929797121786,21.6909196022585));
#1343=CARTESIAN_POINT('',(-16.8064184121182,-2.60714358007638,21.8592069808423));
#1344=CARTESIAN_POINT('',(-16.5760436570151,-2.60311809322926,22.3757154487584));
#1345=CARTESIAN_POINT('',(-16.4463279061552,-2.60376545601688,22.7327987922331));
#1346=CARTESIAN_POINT('',(-16.3111238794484,-2.60558962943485,23.2492659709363));
#1347=CARTESIAN_POINT('',(-16.2774293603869,-2.60623171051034,23.401507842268));
#1348=CARTESIAN_POINT('',(-16.2226438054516,-2.60741948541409,23.7082136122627));
#1349=CARTESIAN_POINT('',(-16.2015461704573,-2.60796522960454,23.8626763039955));
#1350=CARTESIAN_POINT('',(-16.1728384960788,-2.60873412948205,24.1720064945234));
#1351=CARTESIAN_POINT('',(-16.1651549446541,-2.60895904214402,24.3268670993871));
#1352=CARTESIAN_POINT('',(-16.1633150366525,-2.60901456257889,24.6366432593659));
#1353=CARTESIAN_POINT('',(-16.1691588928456,-2.60884516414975,24.791558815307));
#1354=CARTESIAN_POINT('',(-16.2067663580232,-2.60780469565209,25.254174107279));
#1355=CARTESIAN_POINT('',(-16.2585447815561,-2.60640291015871,25.5604124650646));
#1356=CARTESIAN_POINT('',(-16.408677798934,-2.6041929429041,26.1623826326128));
#1357=CARTESIAN_POINT('',(-16.5072746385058,-2.60338790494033,26.4580510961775));
#1358=CARTESIAN_POINT('',(-16.7113723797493,-2.60518732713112,26.962632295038));
#1359=CARTESIAN_POINT('',(-16.8090508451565,-2.60699326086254,27.1748260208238));
#1360=CARTESIAN_POINT('',(-17.0197513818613,-2.61383210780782,27.5889785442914));
#1361=CARTESIAN_POINT('',(-17.1326231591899,-2.61883501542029,27.7910138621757));
#1362=CARTESIAN_POINT('',(-17.2515916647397,-2.62601624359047,27.9890614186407));
#1363=B_SPLINE_CURVE_WITH_KNOTS('',3,(#1339,#1340,#1341,#1342,#1343,#1344,#1345,#1346,#1347,
#1348,#1349,#1350,#1351,#1352,#1353,#1354,#1355,#1356,#1357,#1358,#1359,#1360,#1361,#1362),
.UNSPECIFIED.,.F.,.F.,(4,2,2,2,2,2,2,2,2,2,2,4),(0.,0.560608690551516,1.12246406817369,
2.25597729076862,2.72334272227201,3.19046310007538,3.65501542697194,4.11957506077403,
5.04670400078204,5.97868320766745,6.67876235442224,7.37236544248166),.UNSPECIFIED.);
#1364=EDGE_CURVE('E28',#1240,#1323,#1363,.T.);
#1365=ORIENTED_EDGE('',*,*,#1364,.F.);
#1366=ORIENTED_EDGE('',*,*,#1241,.F.);
#1367=ORIENTED_EDGE('',*,*,#176,.F.);
#1368=ORIENTED_EDGE('',*,*,#67,.T.);
#1369=ORIENTED_EDGE('',*,*,#933,.T.);
#1370=ORIENTED_EDGE('',*,*,#705,.T.);
#1371=ORIENTED_EDGE('',*,*,#1326,.F.);
#1372=EDGE_LOOP('',(#1365,#1366,#1367,#1368,#1369,#1370,#1371));
#1373=FACE_BOUND('',#1372,.T.);
#1374=ADVANCED_FACE('F194',(#1373),#1338,.F.);
#1375=CARTESIAN_POINT('',(16.5160135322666,-14.8706062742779,-6.26382242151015));
#1376=DIRECTION('',(0.,0.,1.));
#1377=DIRECTION('',(0.,-1.,0.));
#1378=AXIS2_PLACEMENT_3D('',#1375,#1376,#1377);
#1379=CYLINDRICAL_SURFACE('',#1378,12.2666645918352);
#1380=DIRECTION('',(0.,0.,1.));
#1381=VECTOR('',#1380,1.);
#1382=CARTESIAN_POINT('',(17.2513916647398,-2.62600423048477,-6.26382242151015));
#1383=LINE('',#1382,#1381);
#1384=CARTESIAN_POINT('',(17.2513916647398,-2.62600423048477,21.0375722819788));
#1385=VERTEX_POINT('',#1384);
#1386=EDGE_CURVE('E233',#1133,#1385,#1383,.T.);
#1387=ORIENTED_EDGE('',*,*,#1386,.T.);
#1388=CARTESIAN_POINT('',(17.2515916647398,-2.62601624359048,21.0372395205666));
#1389=CARTESIAN_POINT('',(17.155383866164,-2.62022150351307,21.1974244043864));
#1390=CARTESIAN_POINT('',(17.0632330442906,-2.61583941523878,21.3600342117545));
#1391=CARTESIAN_POINT('',(16.8887391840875,-2.60929797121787,21.6909196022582));
#1392=CARTESIAN_POINT('',(16.8064184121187,-2.60714358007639,21.8592069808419));
#1393=CARTESIAN_POINT('',(16.5760436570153,-2.60311809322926,22.3757154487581));
#1394=CARTESIAN_POINT('',(16.4463279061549,-2.60376545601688,22.7327987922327));
#1395=CARTESIAN_POINT('',(16.3111238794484,-2.60558962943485,23.2492659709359));
#1396=CARTESIAN_POINT('',(16.2774293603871,-2.60623171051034,23.4015078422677));
#1397=CARTESIAN_POINT('',(16.2226438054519,-2.60741948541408,23.7082136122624));
#1398=CARTESIAN_POINT('',(16.2015461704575,-2.60796522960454,23.8626763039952));
#1399=CARTESIAN_POINT('',(16.1728384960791,-2.60873412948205,24.1720064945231));
#1400=CARTESIAN_POINT('',(16.1651549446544,-2.60895904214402,24.3268670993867));
#1401=CARTESIAN_POINT('',(16.1633150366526,-2.60901456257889,24.6366432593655));
#1402=CARTESIAN_POINT('',(16.1691588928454,-2.60884516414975,24.7915588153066));
#1403=CARTESIAN_POINT('',(16.2067663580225,-2.60780469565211,25.2541741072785));
#1404=CARTESIAN_POINT('',(16.2585447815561,-2.60640291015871,25.560412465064));
#1405=CARTESIAN_POINT('',(16.4086777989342,-2.60419294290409,26.1623826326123));
#1406=CARTESIAN_POINT('',(16.5072746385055,-2.60338790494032,26.4580510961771));
#1407=CARTESIAN_POINT('',(16.711372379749,-2.60518732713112,26.9626322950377));
#1408=CARTESIAN_POINT('',(16.8090508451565,-2.60699326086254,27.1748260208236));
#1409=CARTESIAN_POINT('',(17.0197513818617,-2.61383210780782,27.5889785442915));
#1410=CARTESIAN_POINT('',(17.1326231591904,-2.6188350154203,27.7910138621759));
#1411=CARTESIAN_POINT('',(17.2515916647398,-2.62601624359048,27.9890614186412));
#1412=B_SPLINE_CURVE_WITH_KNOTS('',3,(#1388,#1389,#1390,#1391,#1392,#1393,#1394,#1395,#1396,
#1397,#1398,#1399,#1400,#1401,#1402,#1403,#1404,#1405,#1406,#1407,#1408,#1409,#1410,#1411),
.UNSPECIFIED.,.F.,.F.,(4,2,2,2,2,2,2,2,2,2,2,4),(0.,0.560608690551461,1.12246406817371,
2.25597729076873,2.7233427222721,3.19046310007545,3.65501542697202,4.11957506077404,
5.046704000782,5.97868320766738,6.67876235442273,7.37236544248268),.UNSPECIFIED.);
#1413=CARTESIAN_POINT('',(17.2513916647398,-2.62600423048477,27.988728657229));
#1414=VERTEX_POINT('',#1413);
#1415=EDGE_CURVE('E214',#1385,#1414,#1412,.T.);
#1416=ORIENTED_EDGE('',*,*,#1415,.T.);
#1417=EDGE_CURVE('E232',#1414,#742,#1383,.T.);
#1418=ORIENTED_EDGE('',*,*,#1417,.T.);
#1419=ORIENTED_EDGE('',*,*,#743,.F.);
#1420=ORIENTED_EDGE('',*,*,#959,.F.);
#1421=ORIENTED_EDGE('',*,*,#1051,.F.);
#1422=ORIENTED_EDGE('',*,*,#1173,.T.);
#1423=EDGE_LOOP('',(#1387,#1416,#1418,#1419,#1420,#1421,#1422));
#1424=FACE_BOUND('',#1423,.T.);
#1425=ADVANCED_FACE('F188',(#1424),#1379,.F.);
#1426=CARTESIAN_POINT('',(10.2946161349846,-118.46157794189,-6.26382242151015));
#1427=DIRECTION('',(0.,0.,1.));
#1428=DIRECTION('',(0.,-1.,0.));
#1429=AXIS2_PLACEMENT_3D('',#1426,#1427,#1428);
#1430=CYLINDRICAL_SURFACE('',#1429,116.044288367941);
#1431=CARTESIAN_POINT('',(17.2511916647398,-2.62599221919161,21.0379050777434));
#1432=CARTESIAN_POINT('',(17.3605509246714,-2.63256021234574,20.8558730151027));
#1433=CARTESIAN_POINT('',(17.4781769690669,-2.63977928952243,20.6788860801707));
#1434=CARTESIAN_POINT('',(17.7285891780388,-2.65558215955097,20.3361701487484));
#1435=CARTESIAN_POINT('',(17.8613680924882,-2.66416530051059,20.1704358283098));
#1436=CARTESIAN_POINT('',(18.1403342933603,-2.68273269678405,19.851771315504));
#1437=CARTESIAN_POINT('',(18.2864734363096,-2.69271198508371,19.6987986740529));
#1438=CARTESIAN_POINT('',(18.5911387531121,-2.71414613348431,19.4059031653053));
#1439=CARTESIAN_POINT('',(18.7496661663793,-2.72560114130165,19.265981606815));
#1440=CARTESIAN_POINT('',(19.2412701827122,-2.76221931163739,18.8673844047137));
#1441=CARTESIAN_POINT('',(19.5910610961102,-2.78968031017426,18.629092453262));
#1442=CARTESIAN_POINT('',(20.3238326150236,-2.85090757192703,18.2118100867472));
#1443=CARTESIAN_POINT('',(20.7068386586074,-2.88467869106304,18.0328656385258));
#1444=CARTESIAN_POINT('',(21.512238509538,-2.96001104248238,17.7306832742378));
#1445=CARTESIAN_POINT('',(21.9356131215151,-3.00184137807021,17.6101220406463));
#1446=CARTESIAN_POINT('',(22.7954871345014,-3.09177206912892,17.4380525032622));
#1447=CARTESIAN_POINT('',(23.2319888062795,-3.13987351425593,17.3865562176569));
#1448=CARTESIAN_POINT('',(24.1298090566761,-3.24404995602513,17.352412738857));
#1449=CARTESIAN_POINT('',(24.5912401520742,-3.30040917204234,17.3734764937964));
#1450=CARTESIAN_POINT('',(25.5036209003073,-3.41734859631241,17.4924935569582));
#1451=CARTESIAN_POINT('',(25.9545689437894,-3.47792944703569,17.5904585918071));
#1452=CARTESIAN_POINT('',(26.8360894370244,-3.60141943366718,17.8628288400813));
#1453=CARTESIAN_POINT('',(27.2664963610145,-3.66434194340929,18.0377665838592));
#1454=CARTESIAN_POINT('',(28.0897613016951,-3.789074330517,18.4612298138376));
#1455=CARTESIAN_POINT('',(28.4826254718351,-3.85088438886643,18.7097432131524));
#1456=CARTESIAN_POINT('',(29.2009277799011,-3.96723220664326,19.2630368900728));
#1457=CARTESIAN_POINT('',(29.5285296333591,-4.02196785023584,19.5649593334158));
#1458=CARTESIAN_POINT('',(30.1237087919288,-4.12359078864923,20.2242762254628));
#1459=CARTESIAN_POINT('',(30.3913170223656,-4.17048212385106,20.5816419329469));
#1460=CARTESIAN_POINT('',(30.8373181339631,-4.24983645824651,21.3128397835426));
#1461=CARTESIAN_POINT('',(31.0209063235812,-4.28311924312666,21.6834132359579));
#1462=CARTESIAN_POINT('',(31.318821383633,-4.33759779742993,22.4522485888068));
#1463=CARTESIAN_POINT('',(31.4331834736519,-4.35879971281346,22.8504962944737));
#1464=CARTESIAN_POINT('',(31.5819417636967,-4.38646265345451,23.632982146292));
#1465=CARTESIAN_POINT('',(31.6214051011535,-4.39385715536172,24.0162299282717));
#1466=CARTESIAN_POINT('',(31.6343122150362,-4.3962706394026,24.7838358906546));
#1467=CARTESIAN_POINT('',(31.6077711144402,-4.39129245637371,25.1681937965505));
#1468=CARTESIAN_POINT('',(31.4916539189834,-4.36966021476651,25.9147246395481));
#1469=CARTESIAN_POINT('',(31.4040395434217,-4.35336958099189,26.2772163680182));
#1470=CARTESIAN_POINT('',(31.1713016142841,-4.31056061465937,26.9825464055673));
#1471=CARTESIAN_POINT('',(31.0261753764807,-4.28404180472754,27.3253837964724));
#1472=CARTESIAN_POINT('',(30.680129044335,-4.22174644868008,27.9896317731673));
#1473=CARTESIAN_POINT('',(30.478130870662,-4.18579203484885,28.3104623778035));
#1474=CARTESIAN_POINT('',(30.0265224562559,-4.10694895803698,28.9156211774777));
#1475=CARTESIAN_POINT('',(29.7769013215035,-4.06405870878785,29.1999409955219));
#1476=CARTESIAN_POINT('',(29.2214742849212,-3.97081569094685,29.7422665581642));
#1477=CARTESIAN_POINT('',(28.913209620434,-3.92017079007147,29.9977012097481));
#1478=CARTESIAN_POINT('',(28.2607761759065,-3.81602372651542,30.4568418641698));
#1479=CARTESIAN_POINT('',(27.9165957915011,-3.76252064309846,30.6605310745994));
#1480=CARTESIAN_POINT('',(27.1748146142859,-3.65092338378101,31.0261640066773));
#1481=CARTESIAN_POINT('',(26.7751452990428,-3.59278264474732,31.1838989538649));
#1482=CARTESIAN_POINT('',(25.9555667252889,-3.47817566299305,31.4338219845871));
#1483=CARTESIAN_POINT('',(25.5356510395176,-3.42170996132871,31.5259891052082));
#1484=CARTESIAN_POINT('',(24.6605018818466,-3.30905170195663,31.6471280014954));
#1485=CARTESIAN_POINT('',(24.2046656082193,-3.25308093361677,31.6719539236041));
#1486=CARTESIAN_POINT('',(23.2941812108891,-3.14680042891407,31.6461183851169));
#1487=CARTESIAN_POINT('',(22.8395332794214,-3.09649155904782,31.5954453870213));
#1488=CARTESIAN_POINT('',(22.1635402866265,-3.02562640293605,31.4625458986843));
#1489=CARTESIAN_POINT('',(21.9367328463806,-3.00254244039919,31.4078302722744));
#1490=CARTESIAN_POINT('',(21.4884958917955,-2.95822534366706,31.2791261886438));
#1491=CARTESIAN_POINT('',(21.2670643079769,-2.93699148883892,31.2051452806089));
#1492=CARTESIAN_POINT('',(20.8311241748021,-2.89641504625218,31.03813731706));
#1493=CARTESIAN_POINT('',(20.6166214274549,-2.87707401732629,30.9450947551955));
#1494=CARTESIAN_POINT('',(20.1965861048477,-2.84033307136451,30.7404574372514));
#1495=CARTESIAN_POINT('',(19.9910494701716,-2.82293227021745,30.6288711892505));
#1496=CARTESIAN_POINT('',(19.5960776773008,-2.79050166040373,30.3909216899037));
#1497=CARTESIAN_POINT('',(19.4063577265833,-2.7754205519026,30.2650383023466));
#1498=CARTESIAN_POINT('',(19.0388353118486,-2.74706092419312,29.9969053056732));
#1499=CARTESIAN_POINT('',(18.8610271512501,-2.73378154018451,29.8546636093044));
#1500=CARTESIAN_POINT('',(18.5192661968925,-2.70899133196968,29.554854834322));
#1501=CARTESIAN_POINT('',(18.3552890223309,-2.69747736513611,29.3973158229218));
#1502=CARTESIAN_POINT('',(18.0426182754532,-2.6761303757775,29.0677691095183));
#1503=CARTESIAN_POINT('',(17.8939151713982,-2.66629630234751,28.8957705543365));
#1504=CARTESIAN_POINT('',(17.6624475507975,-2.65138715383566,28.6009730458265));
#1505=CARTESIAN_POINT('',(17.5748056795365,-2.64585026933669,28.4819960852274));
#1506=CARTESIAN_POINT('',(17.4071874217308,-2.63543572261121,28.238951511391));
#1507=CARTESIAN_POINT('',(17.3272016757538,-2.6305572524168,28.1148903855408));
#1508=CARTESIAN_POINT('',(17.2511916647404,-2.62599221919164,27.9883958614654));
#1509=B_SPLINE_CURVE_WITH_KNOTS('',3,(#1431,#1432,#1433,#1434,#1435,#1436,#1437,#1438,#1439,
#1440,#1441,#1442,#1443,#1444,#1445,#1446,#1447,#1448,#1449,#1450,#1451,#1452,#1453,#1454,#1455,
#1456,#1457,#1458,#1459,#1460,#1461,#1462,#1463,#1464,#1465,#1466,#1467,#1468,#1469,#1470,#1471,
#1472,#1473,#1474,#1475,#1476,#1477,#1478,#1479,#1480,#1481,#1482,#1483,#1484,#1485,#1486,#1487,
#1488,#1489,#1490,#1491,#1492,#1493,#1494,#1495,#1496,#1497,#1498,#1499,#1500,#1501,#1502,#1503,
#1504,#1505,#1506,#1507,#1508),.UNSPECIFIED.,.F.,.F.,(4,2,2,2,2,2,2,2,2,2,2,2,2,2,2,2,2,2,2,2,2,
2,2,2,2,2,2,2,2,2,2,2,2,2,2,2,2,2,4),(0.,0.637081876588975,1.27386019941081,1.90842811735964,
2.54305960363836,3.80922160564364,5.07636201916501,6.39710448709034,7.71807675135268,
9.10758912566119,10.497313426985,11.8968074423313,13.2960716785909,14.6355489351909,
15.9743341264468,17.212452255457,18.4499399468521,19.6002244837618,20.7502454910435,
21.8649336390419,22.9796738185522,24.1171609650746,25.2549086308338,26.4603303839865,
27.6661428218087,28.961255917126,30.2567828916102,31.630430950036,33.0042889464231,
33.7069364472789,34.4093090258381,35.1122552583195,35.814879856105,36.4985491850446,
37.1818891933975,37.8639982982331,38.5456791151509,38.9890396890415,39.4318511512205),.UNSPECIFIED.);
#1510=EDGE_CURVE('E355',#1385,#1414,#1509,.T.);
#1511=ORIENTED_EDGE('',*,*,#1510,.F.);
#1512=ORIENTED_EDGE('',*,*,#1386,.F.);
#1513=ORIENTED_EDGE('',*,*,#1134,.F.);
#1514=ORIENTED_EDGE('',*,*,#635,.F.);
#1515=ORIENTED_EDGE('',*,*,#756,.T.);
#1516=ORIENTED_EDGE('',*,*,#1417,.F.);
#1517=EDGE_LOOP('',(#1511,#1512,#1513,#1514,#1515,#1516));
#1518=FACE_BOUND('',#1517,.T.);
#1519=ADVANCED_FACE('F193',(#1518),#1430,.F.);
#1520=CARTESIAN_POINT('',(-16.5160135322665,14.8706062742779,-6.26382242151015));
#1521=DIRECTION('',(0.,0.,1.));
#1522=DIRECTION('',(0.,-1.,0.));
#1523=AXIS2_PLACEMENT_3D('',#1520,#1521,#1522);
#1524=CYLINDRICAL_SURFACE('',#1523,12.2666645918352);
#1525=DIRECTION('',(0.,0.,1.));
#1526=VECTOR('',#1525,1.);
#1527=CARTESIAN_POINT('',(-17.2513916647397,2.62600423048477,-6.26382242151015));
#1528=LINE('',#1527,#1526);
#1529=CARTESIAN_POINT('',(-17.2513916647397,2.62600423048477,21.0375722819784));
#1530=VERTEX_POINT('',#1529);
#1531=EDGE_CURVE('E150',#222,#1530,#1528,.T.);
#1532=ORIENTED_EDGE('',*,*,#1531,.T.);
#1533=CARTESIAN_POINT('',(-17.2515916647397,2.62601624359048,21.0372395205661));
#1534=CARTESIAN_POINT('',(-17.155383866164,2.62022150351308,21.1974244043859));
#1535=CARTESIAN_POINT('',(-17.0632330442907,2.61583941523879,21.3600342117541));
#1536=CARTESIAN_POINT('',(-16.8887391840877,2.60929797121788,21.6909196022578));
#1537=CARTESIAN_POINT('',(-16.8064184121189,2.60714358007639,21.8592069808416));
#1538=CARTESIAN_POINT('',(-16.5760436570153,2.60311809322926,22.3757154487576));
#1539=CARTESIAN_POINT('',(-16.4463279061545,2.60376545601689,22.7327987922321));
#1540=CARTESIAN_POINT('',(-16.3111238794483,2.60558962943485,23.2492659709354));
#1541=CARTESIAN_POINT('',(-16.2774293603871,2.60623171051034,23.4015078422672));
#1542=CARTESIAN_POINT('',(-16.222643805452,2.60741948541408,23.7082136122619));
#1543=CARTESIAN_POINT('',(-16.2015461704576,2.60796522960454,23.8626763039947));
#1544=CARTESIAN_POINT('',(-16.1728384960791,2.60873412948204,24.1720064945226));
#1545=CARTESIAN_POINT('',(-16.1651549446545,2.60895904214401,24.3268670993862));
#1546=CARTESIAN_POINT('',(-16.1633150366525,2.60901456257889,24.636643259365));
#1547=CARTESIAN_POINT('',(-16.1691588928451,2.60884516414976,24.7915588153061));
#1548=CARTESIAN_POINT('',(-16.2067663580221,2.60780469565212,25.254174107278));
#1549=CARTESIAN_POINT('',(-16.2585447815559,2.60640291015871,25.5604124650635));
#1550=CARTESIAN_POINT('',(-16.4086777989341,2.60419294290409,26.1623826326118));
#1551=CARTESIAN_POINT('',(-16.507274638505,2.60338790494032,26.4580510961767));
#1552=CARTESIAN_POINT('',(-16.7113723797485,2.60518732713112,26.9626322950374));
#1553=CARTESIAN_POINT('',(-16.8090508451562,2.60699326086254,27.1748260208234));
#1554=CARTESIAN_POINT('',(-17.0197513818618,2.61383210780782,27.5889785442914));
#1555=CARTESIAN_POINT('',(-17.1326231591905,2.6188350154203,27.7910138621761));
#1556=CARTESIAN_POINT('',(-17.2515916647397,2.62601624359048,27.9890614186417));
#1557=B_SPLINE_CURVE_WITH_KNOTS('',3,(#1533,#1534,#1535,#1536,#1537,#1538,#1539,#1540,#1541,
#1542,#1543,#1544,#1545,#1546,#1547,#1548,#1549,#1550,#1551,#1552,#1553,#1554,#1555,#1556),
.UNSPECIFIED.,.F.,.F.,(4,2,2,2,2,2,2,2,2,2,2,4),(0.,0.560608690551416,1.12246406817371,
2.25597729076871,2.72334272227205,3.1904631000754,3.65501542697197,4.11957506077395,
5.04670400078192,5.9786832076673,6.67876235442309,7.37236544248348),.UNSPECIFIED.);
#1558=CARTESIAN_POINT('',(-17.2513916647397,2.62600423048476,27.9887286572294));
#1559=VERTEX_POINT('',#1558);
#1560=EDGE_CURVE('E33',#1530,#1559,#1557,.T.);
#1561=ORIENTED_EDGE('',*,*,#1560,.T.);
#1562=EDGE_CURVE('E148',#1559,#659,#1528,.T.);
#1563=ORIENTED_EDGE('',*,*,#1562,.T.);
#1564=ORIENTED_EDGE('',*,*,#837,.F.);
#1565=ORIENTED_EDGE('',*,*,#940,.F.);
#1566=ORIENTED_EDGE('',*,*,#119,.F.);
#1567=ORIENTED_EDGE('',*,*,#262,.T.);
#1568=EDGE_LOOP('',(#1532,#1561,#1563,#1564,#1565,#1566,#1567));
#1569=FACE_BOUND('',#1568,.T.);
#1570=ADVANCED_FACE('F147',(#1569),#1524,.F.);
#1571=CARTESIAN_POINT('',(16.5160135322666,14.8706062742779,-6.26382242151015));
#1572=DIRECTION('',(0.,0.,1.));
#1573=DIRECTION('',(0.,-1.,0.));
#1574=AXIS2_PLACEMENT_3D('',#1571,#1572,#1573);
#1575=CYLINDRICAL_SURFACE('',#1574,12.2666645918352);
#1576=CARTESIAN_POINT('',(17.2515916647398,2.62601624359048,21.0372395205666));
#1577=CARTESIAN_POINT('',(17.155383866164,2.62022150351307,21.1974244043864));
#1578=CARTESIAN_POINT('',(17.0632330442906,2.61583941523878,21.3600342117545));
#1579=CARTESIAN_POINT('',(16.8887391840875,2.60929797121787,21.6909196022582));
#1580=CARTESIAN_POINT('',(16.8064184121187,2.60714358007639,21.8592069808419));
#1581=CARTESIAN_POINT('',(16.5760436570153,2.60311809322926,22.3757154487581));
#1582=CARTESIAN_POINT('',(16.4463279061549,2.60376545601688,22.7327987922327));
#1583=CARTESIAN_POINT('',(16.3111238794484,2.60558962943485,23.2492659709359));
#1584=CARTESIAN_POINT('',(16.2774293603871,2.60623171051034,23.4015078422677));
#1585=CARTESIAN_POINT('',(16.2226438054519,2.60741948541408,23.7082136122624));
#1586=CARTESIAN_POINT('',(16.2015461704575,2.60796522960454,23.8626763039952));
#1587=CARTESIAN_POINT('',(16.1728384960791,2.60873412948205,24.1720064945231));
#1588=CARTESIAN_POINT('',(16.1651549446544,2.60895904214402,24.3268670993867));
#1589=CARTESIAN_POINT('',(16.1633150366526,2.60901456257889,24.6366432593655));
#1590=CARTESIAN_POINT('',(16.1691588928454,2.60884516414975,24.7915588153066));
#1591=CARTESIAN_POINT('',(16.2067663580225,2.60780469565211,25.2541741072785));
#1592=CARTESIAN_POINT('',(16.2585447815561,2.60640291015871,25.560412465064));
#1593=CARTESIAN_POINT('',(16.4086777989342,2.60419294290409,26.1623826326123));
#1594=CARTESIAN_POINT('',(16.5072746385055,2.60338790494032,26.4580510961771));
#1595=CARTESIAN_POINT('',(16.711372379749,2.60518732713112,26.9626322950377));
#1596=CARTESIAN_POINT('',(16.8090508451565,2.60699326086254,27.1748260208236));
#1597=CARTESIAN_POINT('',(17.0197513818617,2.61383210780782,27.5889785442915));
#1598=CARTESIAN_POINT('',(17.1326231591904,2.6188350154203,27.7910138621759));
#1599=CARTESIAN_POINT('',(17.2515916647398,2.62601624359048,27.9890614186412));
#1600=B_SPLINE_CURVE_WITH_KNOTS('',3,(#1576,#1577,#1578,#1579,#1580,#1581,#1582,#1583,#1584,
#1585,#1586,#1587,#1588,#1589,#1590,#1591,#1592,#1593,#1594,#1595,#1596,#1597,#1598,#1599),
.UNSPECIFIED.,.F.,.F.,(4,2,2,2,2,2,2,2,2,2,2,4),(0.,0.560608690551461,1.12246406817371,
2.25597729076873,2.7233427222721,3.19046310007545,3.65501542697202,4.11957506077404,
5.046704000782,5.97868320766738,6.67876235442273,7.37236544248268),.UNSPECIFIED.);
#1601=CARTESIAN_POINT('',(17.2513916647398,2.62600423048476,21.0375722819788));
#1602=VERTEX_POINT('',#1601);
#1603=CARTESIAN_POINT('',(17.2513916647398,2.62600423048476,27.988728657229));
#1604=VERTEX_POINT('',#1603);
#1605=EDGE_CURVE('E223',#1602,#1604,#1600,.T.);
#1606=ORIENTED_EDGE('',*,*,#1605,.F.);
#1607=DIRECTION('',(0.,0.,1.));
#1608=VECTOR('',#1607,1.);
#1609=CARTESIAN_POINT('',(17.2513916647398,2.62600423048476,-6.26382242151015));
#1610=LINE('',#1609,#1608);
#1611=EDGE_CURVE('E237',#1096,#1602,#1610,.T.);
#1612=ORIENTED_EDGE('',*,*,#1611,.F.);
#1613=ORIENTED_EDGE('',*,*,#1097,.F.);
#1614=ORIENTED_EDGE('',*,*,#1006,.T.);
#1615=ORIENTED_EDGE('',*,*,#949,.T.);
#1616=ORIENTED_EDGE('',*,*,#801,.T.);
#1617=EDGE_CURVE('E236',#1604,#771,#1610,.T.);
#1618=ORIENTED_EDGE('',*,*,#1617,.F.);
#1619=EDGE_LOOP('',(#1606,#1612,#1613,#1614,#1615,#1616,#1618));
#1620=FACE_BOUND('',#1619,.T.);
#1621=ADVANCED_FACE('F245',(#1620),#1575,.F.);
#1622=CARTESIAN_POINT('',(-10.2946161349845,118.46157794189,-6.26382242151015));
#1623=DIRECTION('',(0.,0.,1.));
#1624=DIRECTION('',(0.,-1.,0.));
#1625=AXIS2_PLACEMENT_3D('',#1622,#1623,#1624);
#1626=CYLINDRICAL_SURFACE('',#1625,116.044288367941);
#1627=CARTESIAN_POINT('',(-17.2511916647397,2.6259922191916,21.0379050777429));
#1628=CARTESIAN_POINT('',(-17.3605509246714,2.63256021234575,20.8558730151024));
#1629=CARTESIAN_POINT('',(-17.478176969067,2.63977928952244,20.6788860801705));
#1630=CARTESIAN_POINT('',(-17.728589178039,2.65558215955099,20.3361701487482));
#1631=CARTESIAN_POINT('',(-17.8613680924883,2.66416530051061,20.1704358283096));
#1632=CARTESIAN_POINT('',(-18.1403342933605,2.68273269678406,19.8517713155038));
#1633=CARTESIAN_POINT('',(-18.2864734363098,2.69271198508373,19.6987986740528));
#1634=CARTESIAN_POINT('',(-18.5911387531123,2.71414613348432,19.4059031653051));
#1635=CARTESIAN_POINT('',(-18.7496661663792,2.72560114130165,19.2659816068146));
#1636=CARTESIAN_POINT('',(-19.241270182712,2.76221931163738,18.8673844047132));
#1637=CARTESIAN_POINT('',(-19.5910610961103,2.78968031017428,18.6290924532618));
#1638=CARTESIAN_POINT('',(-20.3238326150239,2.85090757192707,18.2118100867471));
#1639=CARTESIAN_POINT('',(-20.7068386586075,2.88467869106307,18.0328656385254));
#1640=CARTESIAN_POINT('',(-21.5122385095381,2.9600110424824,17.7306832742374));
#1641=CARTESIAN_POINT('',(-21.9356131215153,3.00184137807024,17.6101220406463));
#1642=CARTESIAN_POINT('',(-22.7954871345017,3.09177206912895,17.4380525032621));
#1643=CARTESIAN_POINT('',(-23.2319888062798,3.13987351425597,17.3865562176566));
#1644=CARTESIAN_POINT('',(-24.1298090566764,3.24404995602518,17.3524127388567));
#1645=CARTESIAN_POINT('',(-24.5912401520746,3.3004091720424,17.3734764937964));
#1646=CARTESIAN_POINT('',(-25.5036209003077,3.41734859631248,17.4924935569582));
#1647=CARTESIAN_POINT('',(-25.95456894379,3.47792944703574,17.5904585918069));
#1648=CARTESIAN_POINT('',(-26.836089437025,3.60141943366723,17.8628288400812));
#1649=CARTESIAN_POINT('',(-27.2664963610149,3.66434194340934,18.0377665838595));
#1650=CARTESIAN_POINT('',(-28.0897613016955,3.78907433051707,18.4612298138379));
#1651=CARTESIAN_POINT('',(-28.4826254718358,3.85088438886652,18.7097432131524));
#1652=CARTESIAN_POINT('',(-29.2009277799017,3.96723220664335,19.2630368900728));
#1653=CARTESIAN_POINT('',(-29.5285296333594,4.02196785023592,19.564959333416));
#1654=CARTESIAN_POINT('',(-30.1237087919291,4.12359078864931,20.2242762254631));
#1655=CARTESIAN_POINT('',(-30.3913170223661,4.17048212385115,20.5816419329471));
#1656=CARTESIAN_POINT('',(-30.8373181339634,4.24983645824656,21.3128397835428));
#1657=CARTESIAN_POINT('',(-31.0209063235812,4.28311924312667,21.6834132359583));
#1658=CARTESIAN_POINT('',(-31.3188213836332,4.33759779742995,22.4522485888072));
#1659=CARTESIAN_POINT('',(-31.4331834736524,4.35879971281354,22.8504962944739));
#1660=CARTESIAN_POINT('',(-31.5819417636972,4.38646265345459,23.6329821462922));
#1661=CARTESIAN_POINT('',(-31.6214051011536,4.39385715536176,24.016229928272));
#1662=CARTESIAN_POINT('',(-31.6343122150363,4.39627063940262,24.7838358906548));
#1663=CARTESIAN_POINT('',(-31.6077711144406,4.39129245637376,25.1681937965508));
#1664=CARTESIAN_POINT('',(-31.4916539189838,4.36966021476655,25.9147246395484));
#1665=CARTESIAN_POINT('',(-31.4040395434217,4.35336958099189,26.2772163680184));
#1666=CARTESIAN_POINT('',(-31.171301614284,4.31056061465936,26.9825464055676));
#1667=CARTESIAN_POINT('',(-31.0261753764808,4.28404180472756,27.3253837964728));
#1668=CARTESIAN_POINT('',(-30.6801290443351,4.22174644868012,27.9896317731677));
#1669=CARTESIAN_POINT('',(-30.4781308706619,4.18579203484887,28.3104623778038));
#1670=CARTESIAN_POINT('',(-30.0265224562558,4.10694895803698,28.915621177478));
#1671=CARTESIAN_POINT('',(-29.7769013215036,4.06405870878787,29.1999409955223));
#1672=CARTESIAN_POINT('',(-29.2214742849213,3.97081569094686,29.7422665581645));
#1673=CARTESIAN_POINT('',(-28.9132096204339,3.92017079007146,29.9977012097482));
#1674=CARTESIAN_POINT('',(-28.2607761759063,3.81602372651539,30.4568418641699));
#1675=CARTESIAN_POINT('',(-27.9165957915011,3.76252064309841,30.6605310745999));
#1676=CARTESIAN_POINT('',(-27.1748146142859,3.65092338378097,31.0261640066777));
#1677=CARTESIAN_POINT('',(-26.7751452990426,3.5927826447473,31.1838989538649));
#1678=CARTESIAN_POINT('',(-25.9555667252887,3.47817566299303,31.4338219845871));
#1679=CARTESIAN_POINT('',(-25.5356510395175,3.42170996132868,31.5259891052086));
#1680=CARTESIAN_POINT('',(-24.6605018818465,3.3090517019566,31.6471280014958));
#1681=CARTESIAN_POINT('',(-24.2046656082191,3.25308093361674,31.6719539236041));
#1682=CARTESIAN_POINT('',(-23.2941812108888,3.14680042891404,31.6461183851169));
#1683=CARTESIAN_POINT('',(-22.839533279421,3.09649155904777,31.5954453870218));
#1684=CARTESIAN_POINT('',(-22.1635402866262,3.02562640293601,31.4625458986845));
#1685=CARTESIAN_POINT('',(-21.9367328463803,3.00254244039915,31.4078302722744));
#1686=CARTESIAN_POINT('',(-21.4884958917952,2.95822534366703,31.2791261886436));
#1687=CARTESIAN_POINT('',(-21.2670643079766,2.9369914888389,31.2051452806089));
#1688=CARTESIAN_POINT('',(-20.8311241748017,2.89641504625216,31.0381373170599));
#1689=CARTESIAN_POINT('',(-20.6166214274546,2.87707401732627,30.9450947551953));
#1690=CARTESIAN_POINT('',(-20.1965861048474,2.84033307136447,30.7404574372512));
#1691=CARTESIAN_POINT('',(-19.9910494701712,2.82293227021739,30.6288711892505));
#1692=CARTESIAN_POINT('',(-19.5960776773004,2.79050166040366,30.3909216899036));
#1693=CARTESIAN_POINT('',(-19.406357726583,2.77542055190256,30.2650383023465));
#1694=CARTESIAN_POINT('',(-19.0388353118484,2.7470609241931,29.9969053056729));
#1695=CARTESIAN_POINT('',(-18.8610271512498,2.73378154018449,29.8546636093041));
#1696=CARTESIAN_POINT('',(-18.5192661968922,2.70899133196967,29.5548548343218));
#1697=CARTESIAN_POINT('',(-18.3552890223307,2.69747736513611,29.3973158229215));
#1698=CARTESIAN_POINT('',(-18.0426182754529,2.67613037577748,29.0677691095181));
#1699=CARTESIAN_POINT('',(-17.8939151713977,2.66629630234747,28.8957705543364));
#1700=CARTESIAN_POINT('',(-17.6624475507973,2.65138715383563,28.6009730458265));
#1701=CARTESIAN_POINT('',(-17.5748056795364,2.64585026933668,28.4819960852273));
#1702=CARTESIAN_POINT('',(-17.407187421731,2.63543572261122,28.238951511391));
#1703=CARTESIAN_POINT('',(-17.3272016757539,2.63055725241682,28.1148903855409));
#1704=CARTESIAN_POINT('',(-17.2511916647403,2.62599221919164,27.9883958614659));
#1705=B_SPLINE_CURVE_WITH_KNOTS('',3,(#1627,#1628,#1629,#1630,#1631,#1632,#1633,#1634,#1635,
#1636,#1637,#1638,#1639,#1640,#1641,#1642,#1643,#1644,#1645,#1646,#1647,#1648,#1649,#1650,#1651,
#1652,#1653,#1654,#1655,#1656,#1657,#1658,#1659,#1660,#1661,#1662,#1663,#1664,#1665,#1666,#1667,
#1668,#1669,#1670,#1671,#1672,#1673,#1674,#1675,#1676,#1677,#1678,#1679,#1680,#1681,#1682,#1683,
#1684,#1685,#1686,#1687,#1688,#1689,#1690,#1691,#1692,#1693,#1694,#1695,#1696,#1697,#1698,#1699,
#1700,#1701,#1702,#1703,#1704),.UNSPECIFIED.,.F.,.F.,(4,2,2,2,2,2,2,2,2,2,2,2,2,2,2,2,2,2,2,2,2,
2,2,2,2,2,2,2,2,2,2,2,2,2,2,2,2,2,4),(0.,0.637081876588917,1.27386019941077,1.90842811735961,
2.54305960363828,3.80922160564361,5.07636201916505,6.39710448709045,7.71807675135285,
9.10758912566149,10.4973134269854,11.8968074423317,13.2960716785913,14.6355489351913,
15.9743341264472,17.2124522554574,18.4499399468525,19.6002244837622,20.7502454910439,
21.8649336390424,22.9796738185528,24.1171609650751,25.2549086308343,26.460330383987,
27.6661428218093,28.9612559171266,30.2567828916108,31.6304309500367,33.0042889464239,
33.7069364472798,34.4093090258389,35.1122552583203,35.8148798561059,36.4985491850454,
37.1818891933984,37.863998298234,38.5456791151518,38.989039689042,39.4318511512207),.UNSPECIFIED.);
#1706=EDGE_CURVE('E9',#1530,#1559,#1705,.T.);
#1707=ORIENTED_EDGE('',*,*,#1706,.F.);
#1708=ORIENTED_EDGE('',*,*,#1531,.F.);
#1709=ORIENTED_EDGE('',*,*,#223,.F.);
#1710=ORIENTED_EDGE('',*,*,#451,.F.);
#1711=ORIENTED_EDGE('',*,*,#660,.T.);
#1712=ORIENTED_EDGE('',*,*,#1562,.F.);
#1713=EDGE_LOOP('',(#1707,#1708,#1709,#1710,#1711,#1712));
#1714=FACE_BOUND('',#1713,.T.);
#1715=ADVANCED_FACE('F152',(#1714),#1626,.F.);
#1716=CARTESIAN_POINT('',(10.2946161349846,118.46157794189,-6.26382242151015));
#1717=DIRECTION('',(0.,0.,1.));
#1718=DIRECTION('',(0.,-1.,0.));
#1719=AXIS2_PLACEMENT_3D('',#1716,#1717,#1718);
#1720=CYLINDRICAL_SURFACE('',#1719,116.044288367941);
#1721=ORIENTED_EDGE('',*,*,#1611,.T.);
#1722=CARTESIAN_POINT('',(17.2511916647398,2.6259922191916,21.0379050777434));
#1723=CARTESIAN_POINT('',(17.3605509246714,2.63256021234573,20.8558730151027));
#1724=CARTESIAN_POINT('',(17.4781769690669,2.63977928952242,20.6788860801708));
#1725=CARTESIAN_POINT('',(17.7285891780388,2.65558215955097,20.3361701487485));
#1726=CARTESIAN_POINT('',(17.8613680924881,2.6641653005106,20.1704358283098));
#1727=CARTESIAN_POINT('',(18.1403342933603,2.68273269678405,19.851771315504));
#1728=CARTESIAN_POINT('',(18.2864734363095,2.6927119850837,19.698798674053));
#1729=CARTESIAN_POINT('',(18.591138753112,2.7141461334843,19.4059031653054));
#1730=CARTESIAN_POINT('',(18.7496661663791,2.72560114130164,19.265981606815));
#1731=CARTESIAN_POINT('',(19.241270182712,2.76221931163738,18.8673844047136));
#1732=CARTESIAN_POINT('',(19.5910610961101,2.78968031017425,18.629092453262));
#1733=CARTESIAN_POINT('',(20.3238326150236,2.85090757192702,18.2118100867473));
#1734=CARTESIAN_POINT('',(20.7068386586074,2.88467869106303,18.0328656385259));
#1735=CARTESIAN_POINT('',(21.512238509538,2.96001104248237,17.7306832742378));
#1736=CARTESIAN_POINT('',(21.935613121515,3.0018413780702,17.6101220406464));
#1737=CARTESIAN_POINT('',(22.7954871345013,3.09177206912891,17.4380525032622));
#1738=CARTESIAN_POINT('',(23.2319888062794,3.13987351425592,17.3865562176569));
#1739=CARTESIAN_POINT('',(24.129809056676,3.24404995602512,17.352412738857));
#1740=CARTESIAN_POINT('',(24.5912401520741,3.30040917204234,17.3734764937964));
#1741=CARTESIAN_POINT('',(25.5036209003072,3.4173485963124,17.4924935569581));
#1742=CARTESIAN_POINT('',(25.9545689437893,3.47792944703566,17.590458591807));
#1743=CARTESIAN_POINT('',(26.8360894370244,3.60141943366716,17.8628288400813));
#1744=CARTESIAN_POINT('',(27.2664963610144,3.66434194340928,18.0377665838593));
#1745=CARTESIAN_POINT('',(28.089761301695,3.78907433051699,18.4612298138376));
#1746=CARTESIAN_POINT('',(28.4826254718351,3.8508843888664,18.7097432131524));
#1747=CARTESIAN_POINT('',(29.2009277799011,3.96723220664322,19.2630368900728));
#1748=CARTESIAN_POINT('',(29.5285296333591,4.02196785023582,19.5649593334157));
#1749=CARTESIAN_POINT('',(30.1237087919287,4.12359078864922,20.2242762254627));
#1750=CARTESIAN_POINT('',(30.3913170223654,4.17048212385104,20.5816419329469));
#1751=CARTESIAN_POINT('',(30.8373181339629,4.24983645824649,21.3128397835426));
#1752=CARTESIAN_POINT('',(31.0209063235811,4.28311924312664,21.6834132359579));
#1753=CARTESIAN_POINT('',(31.318821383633,4.33759779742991,22.4522485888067));
#1754=CARTESIAN_POINT('',(31.4331834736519,4.35879971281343,22.8504962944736));
#1755=CARTESIAN_POINT('',(31.5819417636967,4.3864626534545,23.6329821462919));
#1756=CARTESIAN_POINT('',(31.6214051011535,4.39385715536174,24.0162299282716));
#1757=CARTESIAN_POINT('',(31.6343122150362,4.3962706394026,24.7838358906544));
#1758=CARTESIAN_POINT('',(31.6077711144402,4.39129245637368,25.1681937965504));
#1759=CARTESIAN_POINT('',(31.4916539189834,4.36966021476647,25.914724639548));
#1760=CARTESIAN_POINT('',(31.4040395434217,4.35336958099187,26.2772163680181));
#1761=CARTESIAN_POINT('',(31.1713016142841,4.31056061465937,26.9825464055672));
#1762=CARTESIAN_POINT('',(31.0261753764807,4.28404180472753,27.3253837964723));
#1763=CARTESIAN_POINT('',(30.680129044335,4.22174644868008,27.9896317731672));
#1764=CARTESIAN_POINT('',(30.4781308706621,4.18579203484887,28.3104623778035));
#1765=CARTESIAN_POINT('',(30.026522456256,4.10694895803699,28.9156211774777));
#1766=CARTESIAN_POINT('',(29.7769013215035,4.06405870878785,29.1999409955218));
#1767=CARTESIAN_POINT('',(29.2214742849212,3.97081569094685,29.742266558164));
#1768=CARTESIAN_POINT('',(28.9132096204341,3.92017079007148,29.997701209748));
#1769=CARTESIAN_POINT('',(28.2607761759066,3.81602372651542,30.4568418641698));
#1770=CARTESIAN_POINT('',(27.9165957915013,3.76252064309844,30.6605310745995));
#1771=CARTESIAN_POINT('',(27.1748146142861,3.650923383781,31.0261640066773));
#1772=CARTESIAN_POINT('',(26.775145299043,3.59278264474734,31.1838989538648));
#1773=CARTESIAN_POINT('',(25.9555667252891,3.47817566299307,31.433821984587));
#1774=CARTESIAN_POINT('',(25.5356510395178,3.4217099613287,31.5259891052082));
#1775=CARTESIAN_POINT('',(24.6605018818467,3.30905170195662,31.6471280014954));
#1776=CARTESIAN_POINT('',(24.2046656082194,3.25308093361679,31.6719539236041));
#1777=CARTESIAN_POINT('',(23.2941812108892,3.14680042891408,31.6461183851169));
#1778=CARTESIAN_POINT('',(22.8395332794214,3.09649155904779,31.5954453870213));
#1779=CARTESIAN_POINT('',(22.1635402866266,3.02562640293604,31.4625458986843));
#1780=CARTESIAN_POINT('',(21.9367328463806,3.00254244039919,31.4078302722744));
#1781=CARTESIAN_POINT('',(21.4884958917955,2.95822534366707,31.2791261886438));
#1782=CARTESIAN_POINT('',(21.267064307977,2.93699148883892,31.205145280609));
#1783=CARTESIAN_POINT('',(20.8311241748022,2.89641504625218,31.03813731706));
#1784=CARTESIAN_POINT('',(20.616621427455,2.87707401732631,30.9450947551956));
#1785=CARTESIAN_POINT('',(20.1965861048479,2.84033307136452,30.7404574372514));
#1786=CARTESIAN_POINT('',(19.9910494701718,2.82293227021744,30.6288711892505));
#1787=CARTESIAN_POINT('',(19.596077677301,2.7905016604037,30.3909216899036));
#1788=CARTESIAN_POINT('',(19.4063577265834,2.77542055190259,30.2650383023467));
#1789=CARTESIAN_POINT('',(19.0388353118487,2.74706092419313,29.9969053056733));
#1790=CARTESIAN_POINT('',(18.8610271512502,2.73378154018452,29.8546636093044));
#1791=CARTESIAN_POINT('',(18.5192661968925,2.70899133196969,29.5548548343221));
#1792=CARTESIAN_POINT('',(18.355289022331,2.69747736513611,29.3973158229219));
#1793=CARTESIAN_POINT('',(18.0426182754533,2.6761303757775,29.0677691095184));
#1794=CARTESIAN_POINT('',(17.8939151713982,2.6662963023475,28.8957705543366));
#1795=CARTESIAN_POINT('',(17.6624475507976,2.65138715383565,28.6009730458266));
#1796=CARTESIAN_POINT('',(17.5748056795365,2.64585026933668,28.4819960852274));
#1797=CARTESIAN_POINT('',(17.4071874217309,2.6354357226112,28.238951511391));
#1798=CARTESIAN_POINT('',(17.3272016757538,2.6305572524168,28.1148903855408));
#1799=CARTESIAN_POINT('',(17.2511916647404,2.62599221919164,27.9883958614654));
#1800=B_SPLINE_CURVE_WITH_KNOTS('',3,(#1722,#1723,#1724,#1725,#1726,#1727,#1728,#1729,#1730,
#1731,#1732,#1733,#1734,#1735,#1736,#1737,#1738,#1739,#1740,#1741,#1742,#1743,#1744,#1745,#1746,
#1747,#1748,#1749,#1750,#1751,#1752,#1753,#1754,#1755,#1756,#1757,#1758,#1759,#1760,#1761,#1762,
#1763,#1764,#1765,#1766,#1767,#1768,#1769,#1770,#1771,#1772,#1773,#1774,#1775,#1776,#1777,#1778,
#1779,#1780,#1781,#1782,#1783,#1784,#1785,#1786,#1787,#1788,#1789,#1790,#1791,#1792,#1793,#1794,
#1795,#1796,#1797,#1798,#1799),.UNSPECIFIED.,.F.,.F.,(4,2,2,2,2,2,2,2,2,2,2,2,2,2,2,2,2,2,2,2,2,
2,2,2,2,2,2,2,2,2,2,2,2,2,2,2,2,2,4),(0.,0.637081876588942,1.27386019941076,1.90842811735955,
2.54305960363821,3.80922160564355,5.076362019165,6.39710448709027,7.71807675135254,
9.1075891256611,10.497313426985,11.8968074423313,13.2960716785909,14.6355489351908,
15.9743341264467,17.2124522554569,18.449939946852,19.6002244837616,20.7502454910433,
21.8649336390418,22.9796738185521,24.1171609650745,25.2549086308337,26.4603303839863,
27.6661428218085,28.9612559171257,30.25678289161,31.6304309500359,33.0042889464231,
33.7069364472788,34.4093090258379,35.1122552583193,35.8148798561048,36.4985491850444,
37.1818891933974,37.863998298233,38.5456791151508,38.9890396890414,39.4318511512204),.UNSPECIFIED.);
#1801=EDGE_CURVE('E365',#1602,#1604,#1800,.T.);
#1802=ORIENTED_EDGE('',*,*,#1801,.T.);
#1803=ORIENTED_EDGE('',*,*,#1617,.T.);
#1804=ORIENTED_EDGE('',*,*,#772,.F.);
#1805=ORIENTED_EDGE('',*,*,#544,.T.);
#1806=ORIENTED_EDGE('',*,*,#1114,.T.);
#1807=EDGE_LOOP('',(#1721,#1802,#1803,#1804,#1805,#1806));
#1808=FACE_BOUND('',#1807,.T.);
#1809=ADVANCED_FACE('F282',(#1808),#1720,.F.);
#1810=CARTESIAN_POINT('',(21.9908821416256,-20.,24.5131504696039));
#1811=DIRECTION('',(0.,-1.,0.));
#1812=DIRECTION('',(1.,0.,0.));
#1813=AXIS2_PLACEMENT_3D('',#1810,#1811,#1812);
#1814=SPHERICAL_SURFACE('',#1813,18.3411597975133);
#1815=ORIENTED_EDGE('',*,*,#1510,.T.);
#1816=ORIENTED_EDGE('',*,*,#1415,.F.);
#1817=EDGE_LOOP('',(#1815,#1816));
#1818=FACE_BOUND('',#1817,.T.);
#1819=ADVANCED_FACE('F196',(#1818),#1814,.F.);
#1820=CARTESIAN_POINT('',(21.9908821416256,20.,24.5131504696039));
#1821=DIRECTION('',(0.,1.,0.));
#1822=DIRECTION('',(1.,0.,0.));
#1823=AXIS2_PLACEMENT_3D('',#1820,#1821,#1822);
#1824=SPHERICAL_SURFACE('',#1823,18.3411597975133);
#1825=ORIENTED_EDGE('',*,*,#1605,.T.);
#1826=ORIENTED_EDGE('',*,*,#1801,.F.);
#1827=EDGE_LOOP('',(#1825,#1826));
#1828=FACE_BOUND('',#1827,.T.);
#1829=ADVANCED_FACE('F376',(#1828),#1824,.F.);
#1830=CARTESIAN_POINT('',(-21.9908821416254,-20.,24.5131504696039));
#1831=DIRECTION('',(0.,-1.,0.));
#1832=DIRECTION('',(-1.,0.,0.));
#1833=AXIS2_PLACEMENT_3D('',#1830,#1831,#1832);
#1834=SPHERICAL_SURFACE('',#1833,18.3411597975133);
#1835=ORIENTED_EDGE('',*,*,#1364,.T.);
#1836=ORIENTED_EDGE('',*,*,#1324,.F.);
#1837=EDGE_LOOP('',(#1835,#1836));
#1838=FACE_BOUND('',#1837,.T.);
#1839=ADVANCED_FACE('F379',(#1838),#1834,.F.);
#1840=CARTESIAN_POINT('',(-21.9908821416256,20.,24.5131504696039));
#1841=DIRECTION('',(0.,1.,0.));
#1842=DIRECTION('',(-1.,0.,0.));
#1843=AXIS2_PLACEMENT_3D('',#1840,#1841,#1842);
#1844=SPHERICAL_SURFACE('',#1843,18.3411597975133);
#1845=ORIENTED_EDGE('',*,*,#1706,.T.);
#1846=ORIENTED_EDGE('',*,*,#1560,.F.);
#1847=EDGE_LOOP('',(#1845,#1846));
#1848=FACE_BOUND('',#1847,.T.);
#1849=ADVANCED_FACE('F141',(#1848),#1844,.F.);
#1850=CLOSED_SHELL('',(#130,#266,#456,#641,#852,#880,#900,#920,#964,#1056,#1177,#1197,#1217,
#1229,#1333,#1374,#1425,#1519,#1570,#1621,#1715,#1809,#1819,#1829,#1839,#1849));
#1851=MANIFOLD_SOLID_BREP('B1',#1850);
#1852=ADVANCED_BREP_SHAPE_REPRESENTATION('',(#18,#1851),#14);
#1853=SHAPE_DEFINITION_REPRESENTATION(#9,#1852);
ENDSEC;
END-ISO-10303-21;
